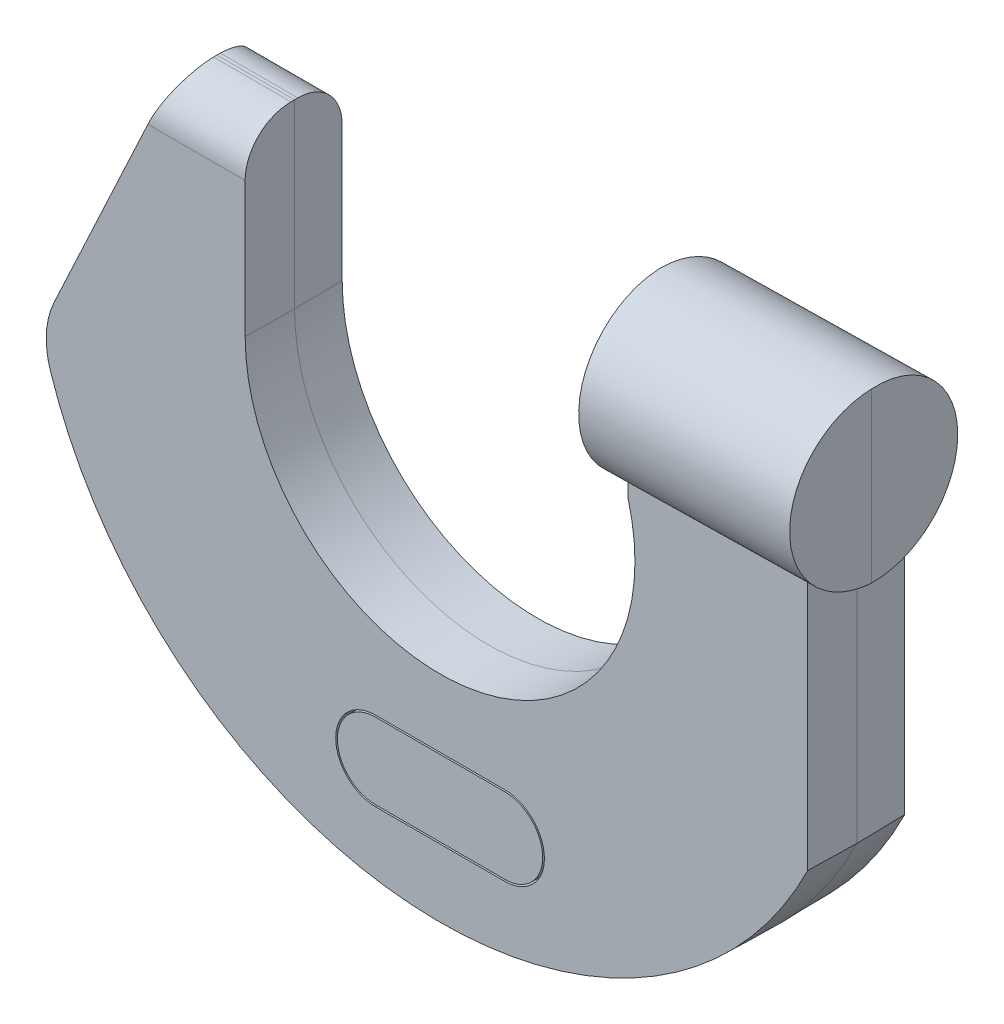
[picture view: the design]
ISO-10303-21;
HEADER;
FILE_DESCRIPTION(('STEP AP214'),'2;1');
FILE_NAME('part.step','',(''),(''),'','','');
FILE_SCHEMA(('AUTOMOTIVE_DESIGN { 1 0 10303 214 1 1 1 1 }'));
ENDSEC;
DATA;
#1=APPLICATION_CONTEXT('core data for automotive mechanical design processes');
#2=APPLICATION_PROTOCOL_DEFINITION('international standard','automotive_design',2000,#1);
#3=PRODUCT_CONTEXT('',#1,'mechanical');
#4=PRODUCT('Part','Part','',(#3));
#5=PRODUCT_RELATED_PRODUCT_CATEGORY('part','',(#4));
#6=PRODUCT_DEFINITION_FORMATION('','',#4);
#7=PRODUCT_DEFINITION_CONTEXT('part definition',#1,'design');
#8=PRODUCT_DEFINITION('design','',#6,#7);
#9=PRODUCT_DEFINITION_SHAPE('','',#8);
#10=(LENGTH_UNIT() NAMED_UNIT(*) SI_UNIT(.MILLI.,.METRE.));
#11=(NAMED_UNIT(*) PLANE_ANGLE_UNIT() SI_UNIT($,.RADIAN.));
#12=(NAMED_UNIT(*) SI_UNIT($,.STERADIAN.) SOLID_ANGLE_UNIT());
#13=UNCERTAINTY_MEASURE_WITH_UNIT(LENGTH_MEASURE(1.E-05),#10,'distance_accuracy_value','');
#14=(GEOMETRIC_REPRESENTATION_CONTEXT(3) GLOBAL_UNCERTAINTY_ASSIGNED_CONTEXT((#13)) GLOBAL_UNIT_ASSIGNED_CONTEXT((#10,
#11,#12)) REPRESENTATION_CONTEXT('',''));
#15=CARTESIAN_POINT('',(0.,0.,0.));
#16=DIRECTION('',(0.,0.,1.));
#17=DIRECTION('',(1.,0.,0.));
#18=AXIS2_PLACEMENT_3D('',#15,#16,#17);
#19=CARTESIAN_POINT('',(-5.,-20.375,0.));
#20=DIRECTION('',(0.,0.999847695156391,0.0174524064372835));
#21=DIRECTION('',(0.,-0.0174524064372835,0.999847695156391));
#22=AXIS2_PLACEMENT_3D('',#19,#20,#21);
#23=PLANE('',#22);
#24=DIRECTION('',(1.,0.,0.));
#25=VECTOR('',#24,1.);
#26=CARTESIAN_POINT('',(0.,-20.375,0.));
#27=LINE('',#26,#25);
#28=CARTESIAN_POINT('',(-5.,-20.375,0.));
#29=VERTEX_POINT('',#28);
#30=CARTESIAN_POINT('',(5.,-20.375,0.));
#31=VERTEX_POINT('',#30);
#32=EDGE_CURVE('E196',#29,#31,#27,.T.);
#33=ORIENTED_EDGE('',*,*,#32,.F.);
#34=DIRECTION('',(0.,0.0174524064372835,-0.999847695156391));
#35=VECTOR('',#34,1.);
#36=CARTESIAN_POINT('',(-5.,-20.375,0.));
#37=LINE('',#36,#35);
#38=CARTESIAN_POINT('',(-5.,-20.4404564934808,3.75));
#39=VERTEX_POINT('',#38);
#40=EDGE_CURVE('E203',#39,#29,#37,.T.);
#41=ORIENTED_EDGE('',*,*,#40,.F.);
#42=DIRECTION('',(1.,0.,0.));
#43=VECTOR('',#42,1.);
#44=CARTESIAN_POINT('',(-5.,-20.4404564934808,3.75));
#45=LINE('',#44,#43);
#46=CARTESIAN_POINT('',(5.,-20.4404564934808,3.75));
#47=VERTEX_POINT('',#46);
#48=EDGE_CURVE('E187',#39,#47,#45,.T.);
#49=ORIENTED_EDGE('',*,*,#48,.T.);
#50=DIRECTION('',(0.,0.0174524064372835,-0.999847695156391));
#51=VECTOR('',#50,1.);
#52=CARTESIAN_POINT('',(5.,-20.375,0.));
#53=LINE('',#52,#51);
#54=EDGE_CURVE('E198',#47,#31,#53,.T.);
#55=ORIENTED_EDGE('',*,*,#54,.T.);
#56=EDGE_LOOP('',(#33,#41,#49,#55));
#57=FACE_BOUND('',#56,.T.);
#58=ADVANCED_FACE('F126',(#57),#23,.T.);
#59=CARTESIAN_POINT('',(-5.,-23.375,0.));
#60=DIRECTION('',(0.,0.,-1.));
#61=DIRECTION('',(1.,0.,0.));
#62=AXIS2_PLACEMENT_3D('',#59,#60,#61);
#63=CONICAL_SURFACE('',#62,3.,0.0174532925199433);
#64=CARTESIAN_POINT('',(-5.,-23.375,0.));
#65=DIRECTION('',(0.,0.,1.));
#66=DIRECTION('',(1.,0.,0.));
#67=AXIS2_PLACEMENT_3D('',#64,#65,#66);
#68=CIRCLE('',#67,3.);
#69=CARTESIAN_POINT('',(-5.,-26.375,0.));
#70=VERTEX_POINT('',#69);
#71=EDGE_CURVE('E195',#29,#70,#68,.T.);
#72=ORIENTED_EDGE('',*,*,#71,.T.);
#73=DIRECTION('',(0.,-0.0174524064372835,-0.999847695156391));
#74=VECTOR('',#73,1.);
#75=CARTESIAN_POINT('',(-5.,-26.375,0.));
#76=LINE('',#75,#74);
#77=CARTESIAN_POINT('',(-5.,-26.3095435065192,3.75));
#78=VERTEX_POINT('',#77);
#79=EDGE_CURVE('E177',#78,#70,#76,.T.);
#80=ORIENTED_EDGE('',*,*,#79,.F.);
#81=CARTESIAN_POINT('',(-5.,-23.375,3.75));
#82=DIRECTION('',(0.,0.,1.));
#83=DIRECTION('',(1.,0.,0.));
#84=AXIS2_PLACEMENT_3D('',#81,#82,#83);
#85=CIRCLE('',#84,2.93454350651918);
#86=EDGE_CURVE('E181',#39,#78,#85,.T.);
#87=ORIENTED_EDGE('',*,*,#86,.F.);
#88=ORIENTED_EDGE('',*,*,#40,.T.);
#89=EDGE_LOOP('',(#72,#80,#87,#88));
#90=FACE_BOUND('',#89,.T.);
#91=ADVANCED_FACE('F193',(#90),#63,.T.);
#92=CARTESIAN_POINT('',(-5.,-23.375,3.75));
#93=DIRECTION('',(0.,0.,1.));
#94=DIRECTION('',(1.,0.,0.));
#95=AXIS2_PLACEMENT_3D('',#92,#93,#94);
#96=PLANE('',#95);
#97=ORIENTED_EDGE('',*,*,#86,.T.);
#98=DIRECTION('',(-1.,0.,0.));
#99=VECTOR('',#98,1.);
#100=CARTESIAN_POINT('',(-5.,-26.3095435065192,3.75));
#101=LINE('',#100,#99);
#102=CARTESIAN_POINT('',(5.,-26.3095435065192,3.75));
#103=VERTEX_POINT('',#102);
#104=EDGE_CURVE('E169',#78,#103,#101,.F.);
#105=ORIENTED_EDGE('',*,*,#104,.T.);
#106=CARTESIAN_POINT('',(5.,-23.375,3.75));
#107=DIRECTION('',(0.,0.,1.));
#108=DIRECTION('',(1.,0.,0.));
#109=AXIS2_PLACEMENT_3D('',#106,#107,#108);
#110=CIRCLE('',#109,2.93454350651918);
#111=EDGE_CURVE('E182',#103,#47,#110,.T.);
#112=ORIENTED_EDGE('',*,*,#111,.T.);
#113=ORIENTED_EDGE('',*,*,#48,.F.);
#114=EDGE_LOOP('',(#97,#105,#112,#113));
#115=FACE_BOUND('',#114,.T.);
#116=ADVANCED_FACE('F128',(#115),#96,.T.);
#117=CARTESIAN_POINT('',(5.,-23.375,0.));
#118=DIRECTION('',(0.,0.,-1.));
#119=DIRECTION('',(1.,0.,0.));
#120=AXIS2_PLACEMENT_3D('',#117,#118,#119);
#121=CONICAL_SURFACE('',#120,3.,0.0174532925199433);
#122=CARTESIAN_POINT('',(5.,-23.375,0.));
#123=DIRECTION('',(0.,0.,1.));
#124=DIRECTION('',(1.,0.,0.));
#125=AXIS2_PLACEMENT_3D('',#122,#123,#124);
#126=CIRCLE('',#125,3.);
#127=CARTESIAN_POINT('',(5.,-26.375,0.));
#128=VERTEX_POINT('',#127);
#129=EDGE_CURVE('E130',#128,#31,#126,.T.);
#130=ORIENTED_EDGE('',*,*,#129,.T.);
#131=ORIENTED_EDGE('',*,*,#54,.F.);
#132=ORIENTED_EDGE('',*,*,#111,.F.);
#133=DIRECTION('',(0.,-0.0174524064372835,-0.999847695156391));
#134=VECTOR('',#133,1.);
#135=CARTESIAN_POINT('',(5.,-26.375,0.));
#136=LINE('',#135,#134);
#137=EDGE_CURVE('E179',#103,#128,#136,.T.);
#138=ORIENTED_EDGE('',*,*,#137,.T.);
#139=EDGE_LOOP('',(#130,#131,#132,#138));
#140=FACE_BOUND('',#139,.T.);
#141=ADVANCED_FACE('F213',(#140),#121,.T.);
#142=CARTESIAN_POINT('',(-5.,-26.375,0.));
#143=DIRECTION('',(0.,-0.999847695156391,0.0174524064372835));
#144=DIRECTION('',(0.,-0.0174524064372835,-0.999847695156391));
#145=AXIS2_PLACEMENT_3D('',#142,#143,#144);
#146=PLANE('',#145);
#147=DIRECTION('',(1.,0.,0.));
#148=VECTOR('',#147,1.);
#149=CARTESIAN_POINT('',(0.,-26.375,0.));
#150=LINE('',#149,#148);
#151=EDGE_CURVE('E206',#70,#128,#150,.T.);
#152=ORIENTED_EDGE('',*,*,#151,.T.);
#153=ORIENTED_EDGE('',*,*,#137,.F.);
#154=ORIENTED_EDGE('',*,*,#104,.F.);
#155=ORIENTED_EDGE('',*,*,#79,.T.);
#156=EDGE_LOOP('',(#152,#153,#154,#155));
#157=FACE_BOUND('',#156,.T.);
#158=ADVANCED_FACE('F174',(#157),#146,.T.);
#159=CARTESIAN_POINT('',(-5.,-26.375,0.));
#160=DIRECTION('',(0.,-0.999847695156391,-0.0174524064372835));
#161=DIRECTION('',(0.,0.0174524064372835,-0.999847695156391));
#162=AXIS2_PLACEMENT_3D('',#159,#160,#161);
#163=PLANE('',#162);
#164=ORIENTED_EDGE('',*,*,#151,.F.);
#165=DIRECTION('',(0.,-0.0174524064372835,0.999847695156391));
#166=VECTOR('',#165,1.);
#167=CARTESIAN_POINT('',(-5.,-26.375,0.));
#168=LINE('',#167,#166);
#169=CARTESIAN_POINT('',(-5.,-26.3095435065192,-3.75));
#170=VERTEX_POINT('',#169);
#171=EDGE_CURVE('E145',#170,#70,#168,.T.);
#172=ORIENTED_EDGE('',*,*,#171,.F.);
#173=DIRECTION('',(1.,0.,0.));
#174=VECTOR('',#173,1.);
#175=CARTESIAN_POINT('',(-5.,-26.3095435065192,-3.75));
#176=LINE('',#175,#174);
#177=CARTESIAN_POINT('',(5.,-26.3095435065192,-3.75));
#178=VERTEX_POINT('',#177);
#179=EDGE_CURVE('E136',#170,#178,#176,.T.);
#180=ORIENTED_EDGE('',*,*,#179,.T.);
#181=DIRECTION('',(0.,-0.0174524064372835,0.999847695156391));
#182=VECTOR('',#181,1.);
#183=CARTESIAN_POINT('',(5.,-26.375,0.));
#184=LINE('',#183,#182);
#185=EDGE_CURVE('E221',#178,#128,#184,.T.);
#186=ORIENTED_EDGE('',*,*,#185,.T.);
#187=EDGE_LOOP('',(#164,#172,#180,#186));
#188=FACE_BOUND('',#187,.T.);
#189=ADVANCED_FACE('F246',(#188),#163,.T.);
#190=CARTESIAN_POINT('',(-5.,-23.375,0.));
#191=DIRECTION('',(0.,0.,1.));
#192=DIRECTION('',(1.,0.,0.));
#193=AXIS2_PLACEMENT_3D('',#190,#191,#192);
#194=CONICAL_SURFACE('',#193,3.,0.0174532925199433);
#195=ORIENTED_EDGE('',*,*,#71,.F.);
#196=DIRECTION('',(0.,0.0174524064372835,0.999847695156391));
#197=VECTOR('',#196,1.);
#198=CARTESIAN_POINT('',(-5.,-20.375,0.));
#199=LINE('',#198,#197);
#200=CARTESIAN_POINT('',(-5.,-20.4404564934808,-3.75));
#201=VERTEX_POINT('',#200);
#202=EDGE_CURVE('E190',#201,#29,#199,.T.);
#203=ORIENTED_EDGE('',*,*,#202,.F.);
#204=CARTESIAN_POINT('',(-5.,-23.375,-3.75));
#205=DIRECTION('',(0.,0.,1.));
#206=DIRECTION('',(1.,0.,0.));
#207=AXIS2_PLACEMENT_3D('',#204,#205,#206);
#208=CIRCLE('',#207,2.93454350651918);
#209=EDGE_CURVE('E13',#201,#170,#208,.T.);
#210=ORIENTED_EDGE('',*,*,#209,.T.);
#211=ORIENTED_EDGE('',*,*,#171,.T.);
#212=EDGE_LOOP('',(#195,#203,#210,#211));
#213=FACE_BOUND('',#212,.T.);
#214=ADVANCED_FACE('F236',(#213),#194,.T.);
#215=CARTESIAN_POINT('',(-5.,-23.375,-3.75));
#216=DIRECTION('',(0.,0.,1.));
#217=DIRECTION('',(1.,0.,0.));
#218=AXIS2_PLACEMENT_3D('',#215,#216,#217);
#219=PLANE('',#218);
#220=ORIENTED_EDGE('',*,*,#209,.F.);
#221=DIRECTION('',(-1.,0.,0.));
#222=VECTOR('',#221,1.);
#223=CARTESIAN_POINT('',(-5.,-20.4404564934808,-3.75));
#224=LINE('',#223,#222);
#225=CARTESIAN_POINT('',(5.,-20.4404564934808,-3.75));
#226=VERTEX_POINT('',#225);
#227=EDGE_CURVE('E232',#201,#226,#224,.F.);
#228=ORIENTED_EDGE('',*,*,#227,.T.);
#229=CARTESIAN_POINT('',(5.,-23.375,-3.75));
#230=DIRECTION('',(0.,0.,1.));
#231=DIRECTION('',(1.,0.,0.));
#232=AXIS2_PLACEMENT_3D('',#229,#230,#231);
#233=CIRCLE('',#232,2.93454350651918);
#234=EDGE_CURVE('E238',#178,#226,#233,.T.);
#235=ORIENTED_EDGE('',*,*,#234,.F.);
#236=ORIENTED_EDGE('',*,*,#179,.F.);
#237=EDGE_LOOP('',(#220,#228,#235,#236));
#238=FACE_BOUND('',#237,.T.);
#239=ADVANCED_FACE('F248',(#238),#219,.F.);
#240=CARTESIAN_POINT('',(5.,-23.375,0.));
#241=DIRECTION('',(0.,0.,1.));
#242=DIRECTION('',(1.,0.,0.));
#243=AXIS2_PLACEMENT_3D('',#240,#241,#242);
#244=CONICAL_SURFACE('',#243,3.,0.0174532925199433);
#245=ORIENTED_EDGE('',*,*,#129,.F.);
#246=ORIENTED_EDGE('',*,*,#185,.F.);
#247=ORIENTED_EDGE('',*,*,#234,.T.);
#248=DIRECTION('',(0.,0.0174524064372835,0.999847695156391));
#249=VECTOR('',#248,1.);
#250=CARTESIAN_POINT('',(5.,-20.375,0.));
#251=LINE('',#250,#249);
#252=EDGE_CURVE('E224',#226,#31,#251,.T.);
#253=ORIENTED_EDGE('',*,*,#252,.T.);
#254=EDGE_LOOP('',(#245,#246,#247,#253));
#255=FACE_BOUND('',#254,.T.);
#256=ADVANCED_FACE('F219',(#255),#244,.T.);
#257=CARTESIAN_POINT('',(-5.,-20.375,0.));
#258=DIRECTION('',(0.,0.999847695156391,-0.0174524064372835));
#259=DIRECTION('',(0.,0.0174524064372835,0.999847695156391));
#260=AXIS2_PLACEMENT_3D('',#257,#258,#259);
#261=PLANE('',#260);
#262=ORIENTED_EDGE('',*,*,#32,.T.);
#263=ORIENTED_EDGE('',*,*,#252,.F.);
#264=ORIENTED_EDGE('',*,*,#227,.F.);
#265=ORIENTED_EDGE('',*,*,#202,.T.);
#266=EDGE_LOOP('',(#262,#263,#264,#265));
#267=FACE_BOUND('',#266,.T.);
#268=ADVANCED_FACE('F231',(#267),#261,.T.);
#269=CLOSED_SHELL('',(#58,#91,#116,#141,#158,#189,#214,#239,#256,#268));
#270=MANIFOLD_SOLID_BREP('B2',#269);
#271=CARTESIAN_POINT('',(-30.1777049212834,-9.89026670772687,0.4026619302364));
#272=CARTESIAN_POINT('',(-30.1827575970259,-9.8747691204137,0.40266193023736));
#273=CARTESIAN_POINT('',(-30.1878102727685,-9.85927153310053,0.402661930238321));
#274=CARTESIAN_POINT('',(-30.1928629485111,-9.84377394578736,0.402661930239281));
#275=CARTESIAN_POINT('',(-30.4454967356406,-9.06889458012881,0.4026619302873));
#276=CARTESIAN_POINT('',(-30.5507182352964,-8.24652745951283,0.402762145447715));
#277=CARTESIAN_POINT('',(-30.4520398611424,-6.61978235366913,0.402762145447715));
#278=CARTESIAN_POINT('',(-30.2481864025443,-5.81616891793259,0.402661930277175));
#279=CARTESIAN_POINT('',(-29.9037472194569,-5.07751670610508,0.402661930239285));
#280=CARTESIAN_POINT('',(-29.8968584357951,-5.06274366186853,0.402661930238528));
#281=CARTESIAN_POINT('',(-29.8899696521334,-5.04797061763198,0.40266193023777));
#282=CARTESIAN_POINT('',(-29.8830808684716,-5.03319757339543,0.402661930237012));
#283=CARTESIAN_POINT('',(-30.0898750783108,-9.86089944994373,-4.90278218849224));
#284=CARTESIAN_POINT('',(-30.0948558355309,-9.84562245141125,-4.90278218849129));
#285=CARTESIAN_POINT('',(-30.099836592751,-9.83034545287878,-4.90278218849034));
#286=CARTESIAN_POINT('',(-30.1048173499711,-9.8150684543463,-4.9027821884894));
#287=CARTESIAN_POINT('',(-30.3538552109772,-9.05121852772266,-4.90278218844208));
#288=CARTESIAN_POINT('',(-30.4575789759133,-8.24055706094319,-4.90268197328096));
#289=CARTESIAN_POINT('',(-30.3603051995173,-6.6369672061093,-4.90268197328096));
#290=CARTESIAN_POINT('',(-30.1593534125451,-5.84479248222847,-4.90278218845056));
#291=CARTESIAN_POINT('',(-29.819816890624,-5.11665406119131,-4.90278218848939));
#292=CARTESIAN_POINT('',(-29.8130261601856,-5.10209129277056,-4.90278218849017));
#293=CARTESIAN_POINT('',(-29.8062354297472,-5.08752852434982,-4.90278218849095));
#294=CARTESIAN_POINT('',(-29.7994446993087,-5.07296575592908,-4.90278218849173));
#295=B_SPLINE_SURFACE_WITH_KNOTS('',1,3,((#271,#272,#273,#274,#275,#276,#277,#278,#279,#280,
#281,#282),(#283,#284,#285,#286,#287,#288,#289,#290,#291,#292,#293,#294)),.UNSPECIFIED.,.F.,.F.,
.F.,(2,2),(4,3,2,3,4),(0.,1.),(-0.01,0.,0.5,1.,1.01),.UNSPECIFIED.);
#296=DIRECTION('',(0.0165928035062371,0.00540974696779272,-0.999847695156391));
#297=VECTOR('',#296,1.);
#298=CARTESIAN_POINT('',(-30.1642253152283,-9.83443372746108,-1.32304419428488));
#299=LINE('',#298,#297);
#300=CARTESIAN_POINT('',(-30.1861806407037,-9.84159531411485,0.));
#301=VERTEX_POINT('',#300);
#302=CARTESIAN_POINT('',(-30.1239477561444,-9.82130687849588,-3.75));
#303=VERTEX_POINT('',#302);
#304=EDGE_CURVE('E398',#301,#303,#299,.T.);
#305=CARTESIAN_POINT('',(-30.171038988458,-9.88803785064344,-2.87920728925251E-12));
#306=CARTESIAN_POINT('',(-30.1760862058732,-9.87255700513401,-1.91985099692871E-12));
#307=CARTESIAN_POINT('',(-30.1811334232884,-9.85707615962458,-9.60548914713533E-13));
#308=CARTESIAN_POINT('',(-30.1861806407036,-9.84159531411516,0.));
#309=CARTESIAN_POINT('',(-30.4385415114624,-9.06755303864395,4.79638030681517E-11));
#310=CARTESIAN_POINT('',(-30.5436493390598,-8.24607433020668,0.000100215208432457));
#311=CARTESIAN_POINT('',(-30.4450775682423,-6.62108661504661,0.000100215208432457));
#312=CARTESIAN_POINT('',(-30.2414443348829,-5.81834133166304,3.79640980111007E-11));
#313=CARTESIAN_POINT('',(-29.8973772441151,-5.08048707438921,0.));
#314=CARTESIAN_POINT('',(-29.8904959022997,-5.06572998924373,-7.56339435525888E-13));
#315=CARTESIAN_POINT('',(-29.8836145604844,-5.05097290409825,-1.51560621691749E-12));
#316=CARTESIAN_POINT('',(-29.876733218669,-5.03621581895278,-2.27487299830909E-12));
#317=B_SPLINE_CURVE_WITH_KNOTS('',3,(#305,#306,#307,#308,#309,#310,#311,#312,#313,#314,#315,
#316),.UNSPECIFIED.,.F.,.F.,(4,3,2,3,4),(-0.01,0.,0.5,1.,1.01),.UNSPECIFIED.);
#318=CARTESIAN_POINT('',(-29.8973772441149,-5.08048707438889,0.));
#319=VERTEX_POINT('',#318);
#320=EDGE_CURVE('E124',#301,#319,#317,.T.);
#321=CARTESIAN_POINT('',(-29.8973772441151,-5.08048707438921,0.));
#322=CARTESIAN_POINT('',(-29.8948994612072,-5.08162692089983,-0.156249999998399));
#323=CARTESIAN_POINT('',(-29.8924216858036,-5.08276678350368,-0.3124999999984));
#324=CARTESIAN_POINT('',(-29.8874661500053,-5.08504654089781,-0.624999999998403));
#325=CARTESIAN_POINT('',(-29.8849883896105,-5.08618643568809,-0.781249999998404));
#326=CARTESIAN_POINT('',(-29.8800328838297,-5.08846625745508,-1.09374999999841));
#327=CARTESIAN_POINT('',(-29.8775551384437,-5.08960618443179,-1.24999999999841));
#328=CARTESIAN_POINT('',(-29.8725996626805,-5.09188607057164,-1.56249999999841));
#329=CARTESIAN_POINT('',(-29.8701219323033,-5.09302602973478,-1.71874999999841));
#330=CARTESIAN_POINT('',(-29.8651664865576,-5.09530598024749,-2.03124999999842));
#331=CARTESIAN_POINT('',(-29.8626887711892,-5.09644597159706,-2.18749999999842));
#332=CARTESIAN_POINT('',(-29.8577333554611,-5.09872598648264,-2.49999999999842));
#333=CARTESIAN_POINT('',(-29.8552556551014,-5.09986601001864,-2.65624999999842));
#334=CARTESIAN_POINT('',(-29.8503002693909,-5.10214608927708,-2.96874999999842));
#335=CARTESIAN_POINT('',(-29.84782258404,-5.10328614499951,-3.12499999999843));
#336=CARTESIAN_POINT('',(-29.842867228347,-5.10556628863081,-3.43749999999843));
#337=CARTESIAN_POINT('',(-29.8403895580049,-5.10670637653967,-3.59374999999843));
#338=CARTESIAN_POINT('',(-29.8379118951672,-5.10784648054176,-3.75));
#339=B_SPLINE_CURVE_WITH_KNOTS('',3,(#321,#322,#323,#324,#325,#326,#327,#328,#329,#330,#331,
#332,#333,#334,#335,#336,#337,#338),.UNSPECIFIED.,.F.,.F.,(4,2,2,2,2,2,2,2,4),(0.,
0.46882140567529,0.937642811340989,1.40646421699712,1.87528562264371,2.34410702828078,
2.81292843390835,3.28174983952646,3.75057124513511),.UNSPECIFIED.);
#340=CARTESIAN_POINT('',(-29.8379118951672,-5.10784648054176,-3.75));
#341=VERTEX_POINT('',#340);
#342=EDGE_CURVE('E519',#341,#319,#339,.F.);
#343=CARTESIAN_POINT('',(-30.1239477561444,-9.82130687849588,-3.75));
#344=CARTESIAN_POINT('',(-30.1885651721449,-9.62302238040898,-3.75));
#345=CARTESIAN_POINT('',(-30.2434313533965,-9.42172796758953,-3.75));
#346=CARTESIAN_POINT('',(-30.3334765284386,-9.01449324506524,-3.75));
#347=CARTESIAN_POINT('',(-30.3686285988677,-8.80854697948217,-3.75));
#348=CARTESIAN_POINT('',(-30.4372160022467,-8.24268287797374,-3.75));
#349=CARTESIAN_POINT('',(-30.4506874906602,-7.88005396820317,-3.75));
#350=CARTESIAN_POINT('',(-30.4248312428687,-7.33869752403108,-3.75));
#351=CARTESIAN_POINT('',(-30.4085013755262,-7.15852291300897,-3.75));
#352=CARTESIAN_POINT('',(-30.3607147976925,-6.8001726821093,-3.75));
#353=CARTESIAN_POINT('',(-30.3292620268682,-6.62199655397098,-3.75));
#354=CARTESIAN_POINT('',(-30.2611399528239,-6.31246037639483,-3.75));
#355=CARTESIAN_POINT('',(-30.2276672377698,-6.18038569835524,-3.75));
#356=CARTESIAN_POINT('',(-30.1712624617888,-5.98406885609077,-3.75));
#357=CARTESIAN_POINT('',(-30.151427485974,-5.91892695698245,-3.75));
#358=CARTESIAN_POINT('',(-30.1097078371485,-5.78930432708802,-3.75));
#359=CARTESIAN_POINT('',(-30.08782324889,-5.72482356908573,-3.75));
#360=CARTESIAN_POINT('',(-30.0420614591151,-5.59670095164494,-3.75));
#361=CARTESIAN_POINT('',(-30.0181878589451,-5.53305780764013,-3.75));
#362=CARTESIAN_POINT('',(-29.9808698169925,-5.43818456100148,-3.75));
#363=CARTESIAN_POINT('',(-29.9681782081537,-5.4066564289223,-3.75));
#364=CARTESIAN_POINT('',(-29.9422965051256,-5.34380684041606,-3.75));
#365=CARTESIAN_POINT('',(-29.9291064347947,-5.31248537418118,-3.75));
#366=CARTESIAN_POINT('',(-29.9022255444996,-5.25006178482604,-3.75));
#367=CARTESIAN_POINT('',(-29.8885347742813,-5.21895964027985,-3.75));
#368=CARTESIAN_POINT('',(-29.8676384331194,-5.17246721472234,-3.75));
#369=CARTESIAN_POINT('',(-29.8606126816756,-5.15699595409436,-3.75));
#370=CARTESIAN_POINT('',(-29.8464160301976,-5.12612002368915,-3.75));
#371=CARTESIAN_POINT('',(-29.8392451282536,-5.1107153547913,-3.75));
#372=CARTESIAN_POINT('',(-29.8248922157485,-5.07991594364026,-3.75));
#373=CARTESIAN_POINT('',(-29.8177102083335,-5.06452119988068,-3.75));
#374=CARTESIAN_POINT('',(-29.803349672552,-5.03373017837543,-3.75));
#375=CARTESIAN_POINT('',(-29.7961711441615,-5.01833390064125,-3.75));
#376=CARTESIAN_POINT('',(-29.7818143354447,-4.98754412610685,-3.75));
#377=CARTESIAN_POINT('',(-29.7746360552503,-4.97215062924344,-3.75));
#378=CARTESIAN_POINT('',(-29.7602794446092,-4.94136352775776,-3.75));
#379=CARTESIAN_POINT('',(-29.7531011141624,-4.92596992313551,-3.75));
#380=CARTESIAN_POINT('',(-29.7459232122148,-4.91057611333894,-3.75));
#381=B_SPLINE_CURVE_WITH_KNOTS('',3,(#343,#344,#345,#346,#347,#348,#349,#350,#351,#352,#353,
#354,#355,#356,#357,#358,#359,#360,#361,#362,#363,#364,#365,#366,#367,#368,#369,#370,#371,#372,
#373,#374,#375,#376,#377,#378,#379,#380),.UNSPECIFIED.,.F.,.F.,(4,2,2,2,2,2,2,2,2,2,2,2,2,2,2,2,
2,2,4),(0.,0.625084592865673,1.2510207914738,2.33363174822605,2.87586935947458,3.41796578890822,
3.82644665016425,4.03070073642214,4.2349463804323,4.43882993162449,4.54078669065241,
4.64273857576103,4.74468035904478,4.79565511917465,4.84663055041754,4.89759351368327,
4.94855612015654,4.99951088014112,5.05046599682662),.UNSPECIFIED.);
#382=EDGE_CURVE('E404',#303,#341,#381,.T.);
#383=ORIENTED_EDGE('',*,*,#304,.F.);
#384=ORIENTED_EDGE('',*,*,#320,.T.);
#385=ORIENTED_EDGE('',*,*,#342,.F.);
#386=ORIENTED_EDGE('',*,*,#382,.F.);
#387=EDGE_LOOP('',(#383,#384,#385,#386));
#388=FACE_BOUND('',#387,.T.);
#389=ADVANCED_FACE('F362',(#388),#295,.F.);
#390=CARTESIAN_POINT('',(13.35,0.,0.));
#391=DIRECTION('',(-0.999847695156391,0.,0.0174524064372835));
#392=DIRECTION('',(0.0174524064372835,0.,0.999847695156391));
#393=AXIS2_PLACEMENT_3D('',#390,#391,#392);
#394=PLANE('',#393);
#395=CARTESIAN_POINT('',(13.35,10.45,0.));
#396=DIRECTION('',(-0.999847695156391,0.,0.0174524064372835));
#397=DIRECTION('',(0.0174524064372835,0.,0.999847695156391));
#398=AXIS2_PLACEMENT_3D('',#395,#396,#397);
#399=CIRCLE('',#398,6.5);
#400=CARTESIAN_POINT('',(13.35,16.95,0.));
#401=VERTEX_POINT('',#400);
#402=CARTESIAN_POINT('',(13.35,3.95,0.));
#403=VERTEX_POINT('',#402);
#404=EDGE_CURVE('E430',#401,#403,#399,.F.);
#405=ORIENTED_EDGE('',*,*,#404,.F.);
#406=DIRECTION('',(0.,-1.,0.));
#407=VECTOR('',#406,1.);
#408=CARTESIAN_POINT('',(13.35,0.,0.));
#409=LINE('',#408,#407);
#410=EDGE_CURVE('E372',#401,#403,#409,.T.);
#411=ORIENTED_EDGE('',*,*,#410,.T.);
#412=EDGE_LOOP('',(#405,#411));
#413=FACE_BOUND('',#412,.T.);
#414=ADVANCED_FACE('F471',(#413),#394,.T.);
#415=CARTESIAN_POINT('',(29.6024753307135,0.,0.));
#416=DIRECTION('',(0.999847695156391,0.,-0.0174524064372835));
#417=DIRECTION('',(-0.0174524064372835,0.,-0.999847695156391));
#418=AXIS2_PLACEMENT_3D('',#415,#416,#417);
#419=PLANE('',#418);
#420=CARTESIAN_POINT('',(29.5975250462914,10.45,-0.283601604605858));
#421=DIRECTION('',(0.999847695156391,0.,-0.0174524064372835));
#422=DIRECTION('',(-0.0174524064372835,0.,-0.999847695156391));
#423=AXIS2_PLACEMENT_3D('',#420,#421,#422);
#424=CIRCLE('',#423,6.5);
#425=CARTESIAN_POINT('',(29.6024753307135,3.95619174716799,0.));
#426=VERTEX_POINT('',#425);
#427=CARTESIAN_POINT('',(29.6024753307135,16.943808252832,0.));
#428=VERTEX_POINT('',#427);
#429=EDGE_CURVE('E420',#426,#428,#424,.T.);
#430=ORIENTED_EDGE('',*,*,#429,.T.);
#431=DIRECTION('',(0.,-1.,0.));
#432=VECTOR('',#431,1.);
#433=CARTESIAN_POINT('',(29.6024753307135,0.,0.));
#434=LINE('',#433,#432);
#435=EDGE_CURVE('E418',#428,#426,#434,.T.);
#436=ORIENTED_EDGE('',*,*,#435,.T.);
#437=EDGE_LOOP('',(#430,#436));
#438=FACE_BOUND('',#437,.T.);
#439=ADVANCED_FACE('F364',(#438),#419,.T.);
#440=CARTESIAN_POINT('',(0.,0.,0.));
#441=DIRECTION('',(0.,0.,-1.));
#442=DIRECTION('',(1.,0.,0.));
#443=AXIS2_PLACEMENT_3D('',#440,#441,#442);
#444=CONICAL_SURFACE('',#443,15.,0.0174532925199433);
#445=CARTESIAN_POINT('',(14.4716828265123,3.95014867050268,-0.063548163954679));
#446=CARTESIAN_POINT('',(14.4713712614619,3.95001904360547,-0.0443729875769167));
#447=CARTESIAN_POINT('',(14.4710365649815,3.94997418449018,-0.0251982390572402));
#448=CARTESIAN_POINT('',(14.4706412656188,3.95001827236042,-0.00401599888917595));
#449=CARTESIAN_POINT('',(14.4706035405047,3.95002338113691,-0.00200808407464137));
#450=CARTESIAN_POINT('',(14.4705655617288,3.95002941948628,-1.73952045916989E-07));
#451=B_SPLINE_CURVE_WITH_KNOTS('',3,(#445,#446,#447,#448,#449,#450),.UNSPECIFIED.,.F.,.F.,(4,2,
4),(0.,0.0575331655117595,0.0635579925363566),.UNSPECIFIED.);
#452=CARTESIAN_POINT('',(14.4716828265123,3.9501486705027,-0.063548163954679));
#453=VERTEX_POINT('',#452);
#454=CARTESIAN_POINT('',(14.4705735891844,3.95002206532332,0.));
#455=VERTEX_POINT('',#454);
#456=EDGE_CURVE('E803',#453,#455,#451,.T.);
#457=ORIENTED_EDGE('',*,*,#456,.F.);
#458=CARTESIAN_POINT('',(14.5360300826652,3.95876354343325,-3.75));
#459=CARTESIAN_POINT('',(14.525120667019,3.95730457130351,-3.12499999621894));
#460=CARTESIAN_POINT('',(14.5142112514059,3.95584478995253,-2.49999999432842));
#461=CARTESIAN_POINT('',(14.4923924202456,3.95292360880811,-1.24999999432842));
#462=CARTESIAN_POINT('',(14.4814830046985,3.95146220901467,-0.624999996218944));
#463=CARTESIAN_POINT('',(14.4705735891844,3.94999999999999,0.));
#464=B_SPLINE_CURVE_WITH_KNOTS('',3,(#458,#459,#460,#461,#462,#463),.UNSPECIFIED.,.F.,.F.,(4,2,
4),(0.,1.87529073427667,3.75058146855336),.UNSPECIFIED.);
#465=CARTESIAN_POINT('',(14.5360300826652,3.95876354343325,-3.75));
#466=VERTEX_POINT('',#465);
#467=EDGE_CURVE('E565',#466,#453,#464,.T.);
#468=ORIENTED_EDGE('',*,*,#467,.F.);
#469=CARTESIAN_POINT('',(0.,0.,-3.75));
#470=DIRECTION('',(0.,0.,1.));
#471=DIRECTION('',(1.,0.,0.));
#472=AXIS2_PLACEMENT_3D('',#469,#470,#471);
#473=CIRCLE('',#472,15.0654564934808);
#474=CARTESIAN_POINT('',(-15.0654564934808,0.,-3.75));
#475=VERTEX_POINT('',#474);
#476=EDGE_CURVE('E956',#475,#466,#473,.T.);
#477=ORIENTED_EDGE('',*,*,#476,.F.);
#478=DIRECTION('',(0.0174524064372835,0.,0.999847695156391));
#479=VECTOR('',#478,1.);
#480=CARTESIAN_POINT('',(-15.,0.,0.));
#481=LINE('',#480,#479);
#482=CARTESIAN_POINT('',(-15.,0.,0.));
#483=VERTEX_POINT('',#482);
#484=EDGE_CURVE('E894',#475,#483,#481,.T.);
#485=ORIENTED_EDGE('',*,*,#484,.T.);
#486=CARTESIAN_POINT('',(0.,0.,0.));
#487=DIRECTION('',(0.,0.,1.));
#488=DIRECTION('',(1.,0.,0.));
#489=AXIS2_PLACEMENT_3D('',#486,#487,#488);
#490=CIRCLE('',#489,15.);
#491=EDGE_CURVE('E626',#483,#455,#490,.T.);
#492=ORIENTED_EDGE('',*,*,#491,.T.);
#493=EDGE_LOOP('',(#457,#468,#477,#485,#492));
#494=FACE_BOUND('',#493,.T.);
#495=ADVANCED_FACE('F891',(#494),#444,.F.);
#496=CARTESIAN_POINT('',(14.4705735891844,0.,0.));
#497=DIRECTION('',(-0.999847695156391,0.,-0.0174524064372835));
#498=DIRECTION('',(-0.0174524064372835,0.,0.999847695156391));
#499=AXIS2_PLACEMENT_3D('',#496,#497,#498);
#500=PLANE('',#499);
#501=CARTESIAN_POINT('',(14.4709151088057,10.45,-0.0195656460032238));
#502=DIRECTION('',(-0.999847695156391,0.,-0.0174524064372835));
#503=DIRECTION('',(-0.0174524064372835,0.,0.999847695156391));
#504=AXIS2_PLACEMENT_3D('',#501,#502,#503);
#505=ELLIPSE('',#504,6.50396203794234,6.5);
#506=CARTESIAN_POINT('',(14.5360300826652,5.12584990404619,-3.75));
#507=VERTEX_POINT('',#506);
#508=EDGE_CURVE('E436',#507,#453,#505,.T.);
#509=ORIENTED_EDGE('',*,*,#508,.F.);
#510=DIRECTION('',(0.,-1.,0.));
#511=VECTOR('',#510,1.);
#512=CARTESIAN_POINT('',(14.5360300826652,0.,-3.75));
#513=LINE('',#512,#511);
#514=EDGE_CURVE('E951',#466,#507,#513,.F.);
#515=ORIENTED_EDGE('',*,*,#514,.F.);
#516=ORIENTED_EDGE('',*,*,#467,.T.);
#517=EDGE_LOOP('',(#509,#515,#516));
#518=FACE_BOUND('',#517,.T.);
#519=ADVANCED_FACE('F750',(#518),#500,.T.);
#520=CARTESIAN_POINT('',(0.,14.,0.));
#521=DIRECTION('',(0.,0.999847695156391,0.0174524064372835));
#522=DIRECTION('',(0.,-0.0174524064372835,0.999847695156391));
#523=AXIS2_PLACEMENT_3D('',#520,#521,#522);
#524=PLANE('',#523);
#525=DIRECTION('',(-0.0111177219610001,0.0174513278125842,-0.999785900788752));
#526=VECTOR('',#525,1.);
#527=CARTESIAN_POINT('',(-20.9995286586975,13.9992601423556,0.0423864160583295));
#528=LINE('',#527,#526);
#529=CARTESIAN_POINT('',(-20.9970870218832,13.9954275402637,0.261956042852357));
#530=VERTEX_POINT('',#529);
#531=CARTESIAN_POINT('',(-21.,14.,0.));
#532=VERTEX_POINT('',#531);
#533=EDGE_CURVE('E701',#530,#532,#528,.T.);
#534=ORIENTED_EDGE('',*,*,#533,.F.);
#535=DIRECTION('',(-1.,0.,0.));
#536=VECTOR('',#535,1.);
#537=CARTESIAN_POINT('',(-15.0654564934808,13.9954275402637,0.261956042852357));
#538=LINE('',#537,#536);
#539=CARTESIAN_POINT('',(-15.0045724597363,13.9954275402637,0.261956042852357));
#540=VERTEX_POINT('',#539);
#541=EDGE_CURVE('E783',#530,#540,#538,.F.);
#542=ORIENTED_EDGE('',*,*,#541,.T.);
#543=DIRECTION('',(0.0174497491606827,0.0174497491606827,-0.999695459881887));
#544=VECTOR('',#543,1.);
#545=CARTESIAN_POINT('',(-14.9954325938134,14.0045674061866,-0.261666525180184));
#546=LINE('',#545,#544);
#547=CARTESIAN_POINT('',(-15.,14.,0.));
#548=VERTEX_POINT('',#547);
#549=EDGE_CURVE('E704',#540,#548,#546,.T.);
#550=ORIENTED_EDGE('',*,*,#549,.T.);
#551=DIRECTION('',(-1.,0.,0.));
#552=VECTOR('',#551,1.);
#553=CARTESIAN_POINT('',(0.,14.,0.));
#554=LINE('',#553,#552);
#555=EDGE_CURVE('E640',#548,#532,#554,.T.);
#556=ORIENTED_EDGE('',*,*,#555,.T.);
#557=EDGE_LOOP('',(#534,#542,#550,#556));
#558=FACE_BOUND('',#557,.T.);
#559=ADVANCED_FACE('F747',(#558),#524,.T.);
#560=CARTESIAN_POINT('',(0.,0.,3.75));
#561=DIRECTION('',(0.,0.,1.));
#562=DIRECTION('',(1.,0.,0.));
#563=AXIS2_PLACEMENT_3D('',#560,#561,#562);
#564=PLANE('',#563);
#565=CARTESIAN_POINT('',(5.,-23.375,3.75));
#566=DIRECTION('',(0.,0.,1.));
#567=DIRECTION('',(1.,0.,0.));
#568=AXIS2_PLACEMENT_3D('',#565,#566,#567);
#569=CIRCLE('',#568,3.06545649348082);
#570=CARTESIAN_POINT('',(5.,-26.4404564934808,3.75));
#571=VERTEX_POINT('',#570);
#572=CARTESIAN_POINT('',(5.,-20.3095435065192,3.75));
#573=VERTEX_POINT('',#572);
#574=EDGE_CURVE('E690',#571,#573,#569,.T.);
#575=ORIENTED_EDGE('',*,*,#574,.F.);
#576=DIRECTION('',(1.,0.,0.));
#577=VECTOR('',#576,1.);
#578=CARTESIAN_POINT('',(0.,-26.4404564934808,3.75));
#579=LINE('',#578,#577);
#580=CARTESIAN_POINT('',(-5.,-26.4404564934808,3.75));
#581=VERTEX_POINT('',#580);
#582=EDGE_CURVE('E693',#581,#571,#579,.T.);
#583=ORIENTED_EDGE('',*,*,#582,.F.);
#584=CARTESIAN_POINT('',(-5.,-23.375,3.75));
#585=DIRECTION('',(0.,0.,1.));
#586=DIRECTION('',(1.,0.,0.));
#587=AXIS2_PLACEMENT_3D('',#584,#585,#586);
#588=CIRCLE('',#587,3.06545649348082);
#589=CARTESIAN_POINT('',(-5.,-20.3095435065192,3.75));
#590=VERTEX_POINT('',#589);
#591=EDGE_CURVE('E697',#590,#581,#588,.T.);
#592=ORIENTED_EDGE('',*,*,#591,.F.);
#593=DIRECTION('',(-1.,0.,0.));
#594=VECTOR('',#593,1.);
#595=CARTESIAN_POINT('',(0.,-20.3095435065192,3.75));
#596=LINE('',#595,#594);
#597=EDGE_CURVE('E675',#590,#573,#596,.F.);
#598=ORIENTED_EDGE('',*,*,#597,.T.);
#599=EDGE_LOOP('',(#575,#583,#592,#598));
#600=FACE_BOUND('',#599,.T.);
#601=DIRECTION('',(0.422618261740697,0.906307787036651,0.));
#602=VECTOR('',#601,1.);
#603=CARTESIAN_POINT('',(-22.5522572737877,10.5162902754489,3.75));
#604=LINE('',#603,#602);
#605=CARTESIAN_POINT('',(-22.5850489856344,10.4459682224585,3.75));
#606=VERTEX_POINT('',#605);
#607=CARTESIAN_POINT('',(-29.8380535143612,-5.10815018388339,3.75));
#608=VERTEX_POINT('',#607);
#609=EDGE_CURVE('E700',#606,#608,#604,.F.);
#610=ORIENTED_EDGE('',*,*,#609,.T.);
#611=CARTESIAN_POINT('',(-29.8380535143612,-5.10815018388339,3.75));
#612=CARTESIAN_POINT('',(-29.925051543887,-5.29478189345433,3.75));
#613=CARTESIAN_POINT('',(-30.0029668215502,-5.48547389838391,3.75));
#614=CARTESIAN_POINT('',(-30.1403068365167,-5.8737185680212,3.75));
#615=CARTESIAN_POINT('',(-30.1997044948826,-6.07128081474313,3.75));
#616=CARTESIAN_POINT('',(-30.3369294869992,-6.62193811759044,3.75));
#617=CARTESIAN_POINT('',(-30.3950194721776,-6.98025792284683,3.75));
#618=CARTESIAN_POINT('',(-30.4361033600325,-7.52083747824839,3.75));
#619=CARTESIAN_POINT('',(-30.4421085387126,-7.70169954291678,3.75));
#620=CARTESIAN_POINT('',(-30.4388457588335,-8.06330667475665,3.75));
#621=CARTESIAN_POINT('',(-30.4295816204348,-8.24405175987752,3.75));
#622=CARTESIAN_POINT('',(-30.4002376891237,-8.5582548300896,3.75));
#623=CARTESIAN_POINT('',(-30.3835114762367,-8.69203772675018,3.75));
#624=CARTESIAN_POINT('',(-30.3521850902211,-8.8917170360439,3.75));
#625=CARTESIAN_POINT('',(-30.3407032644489,-8.95811180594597,3.75));
#626=CARTESIAN_POINT('',(-30.3156681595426,-9.09050921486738,3.75));
#627=CARTESIAN_POINT('',(-30.3021149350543,-9.15651186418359,3.75));
#628=CARTESIAN_POINT('',(-30.2729705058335,-9.28794659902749,3.75));
#629=CARTESIAN_POINT('',(-30.2573828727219,-9.35337947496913,3.75));
#630=CARTESIAN_POINT('',(-30.2324658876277,-9.45113788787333,3.75));
#631=CARTESIAN_POINT('',(-30.2239037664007,-9.4836607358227,3.75));
#632=CARTESIAN_POINT('',(-30.2062691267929,-9.54856675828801,3.75));
#633=CARTESIAN_POINT('',(-30.1971966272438,-9.58094993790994,3.75));
#634=CARTESIAN_POINT('',(-30.1785417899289,-9.64556844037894,3.75));
#635=CARTESIAN_POINT('',(-30.1689594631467,-9.67780376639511,3.75));
#636=CARTESIAN_POINT('',(-30.1542056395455,-9.72604115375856,3.75));
#637=CARTESIAN_POINT('',(-30.149224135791,-9.74210155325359,3.75));
#638=CARTESIAN_POINT('',(-30.1391320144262,-9.77418185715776,3.75));
#639=CARTESIAN_POINT('',(-30.1340213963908,-9.79020176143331,3.75));
#640=CARTESIAN_POINT('',(-30.123682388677,-9.82220015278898,3.75));
#641=CARTESIAN_POINT('',(-30.1184540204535,-9.83817864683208,3.75));
#642=CARTESIAN_POINT('',(-30.1080188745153,-9.8701426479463,3.75));
#643=CARTESIAN_POINT('',(-30.1028120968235,-9.88612815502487,3.75));
#644=CARTESIAN_POINT('',(-30.092393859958,-9.91809521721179,3.75));
#645=CARTESIAN_POINT('',(-30.0871824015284,-9.93407677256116,3.75));
#646=CARTESIAN_POINT('',(-30.0767594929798,-9.9660398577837,3.75));
#647=CARTESIAN_POINT('',(-30.0715480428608,-9.98202138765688,3.75));
#648=CARTESIAN_POINT('',(-30.0663392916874,-9.99800379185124,3.75));
#649=B_SPLINE_CURVE_WITH_KNOTS('',3,(#611,#612,#613,#614,#615,#616,#617,#618,#619,#620,#621,
#622,#623,#624,#625,#626,#627,#628,#629,#630,#631,#632,#633,#634,#635,#636,#637,#638,#639,#640,
#641,#642,#643,#644,#645,#646,#647,#648),.UNSPECIFIED.,.F.,.F.,(4,2,2,2,2,2,2,2,2,2,2,2,2,2,2,2,
2,2,4),(0.,0.61719291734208,1.23528418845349,2.31823981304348,2.86062368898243,3.40287188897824,
3.80708456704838,4.00919605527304,4.21130221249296,4.41305820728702,4.51394781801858,
4.61483370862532,4.71571742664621,4.76616267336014,4.81660808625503,4.86704438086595,
4.91748072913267,4.96791012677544,5.01833944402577),.UNSPECIFIED.);
#650=CARTESIAN_POINT('',(-30.1239480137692,-9.82130608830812,3.75));
#651=VERTEX_POINT('',#650);
#652=EDGE_CURVE('E424',#608,#651,#649,.T.);
#653=ORIENTED_EDGE('',*,*,#652,.T.);
#654=CARTESIAN_POINT('',(0.,0.,3.75));
#655=DIRECTION('',(0.,0.,1.));
#656=DIRECTION('',(1.,0.,0.));
#657=AXIS2_PLACEMENT_3D('',#654,#655,#656);
#658=CIRCLE('',#657,31.6845435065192);
#659=CARTESIAN_POINT('',(28.4139699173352,-14.0198648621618,3.75));
#660=VERTEX_POINT('',#659);
#661=EDGE_CURVE('E823',#651,#660,#658,.T.);
#662=ORIENTED_EDGE('',*,*,#661,.T.);
#663=DIRECTION('',(0.,-1.,0.));
#664=VECTOR('',#663,1.);
#665=CARTESIAN_POINT('',(28.4139699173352,0.,3.75));
#666=LINE('',#665,#664);
#667=CARTESIAN_POINT('',(28.4139699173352,5.33617590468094,3.75));
#668=VERTEX_POINT('',#667);
#669=EDGE_CURVE('E825',#668,#660,#666,.T.);
#670=ORIENTED_EDGE('',*,*,#669,.F.);
#671=CARTESIAN_POINT('',(-201.487356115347,10.45,3.75));
#672=DIRECTION('',(0.,0.,1.));
#673=DIRECTION('',(-1.,0.,0.));
#674=AXIS2_PLACEMENT_3D('',#671,#672,#673);
#675=ELLIPSE('',#674,372.441475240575,6.5);
#676=CARTESIAN_POINT('',(14.5360300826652,5.15508400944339,3.75));
#677=VERTEX_POINT('',#676);
#678=EDGE_CURVE('E862',#668,#677,#675,.F.);
#679=ORIENTED_EDGE('',*,*,#678,.T.);
#680=DIRECTION('',(0.,1.,0.));
#681=VECTOR('',#680,1.);
#682=CARTESIAN_POINT('',(14.5360300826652,0.,3.75));
#683=LINE('',#682,#681);
#684=CARTESIAN_POINT('',(14.5360300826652,3.95876354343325,3.75));
#685=VERTEX_POINT('',#684);
#686=EDGE_CURVE('E826',#685,#677,#683,.T.);
#687=ORIENTED_EDGE('',*,*,#686,.F.);
#688=CARTESIAN_POINT('',(0.,0.,3.75));
#689=DIRECTION('',(0.,0.,1.));
#690=DIRECTION('',(1.,0.,0.));
#691=AXIS2_PLACEMENT_3D('',#688,#689,#690);
#692=CIRCLE('',#691,15.0654564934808);
#693=CARTESIAN_POINT('',(-15.0654564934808,0.,3.75));
#694=VERTEX_POINT('',#693);
#695=EDGE_CURVE('E831',#694,#685,#692,.T.);
#696=ORIENTED_EDGE('',*,*,#695,.F.);
#697=DIRECTION('',(0.,-1.,0.));
#698=VECTOR('',#697,1.);
#699=CARTESIAN_POINT('',(-15.0654564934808,0.,3.75));
#700=LINE('',#699,#698);
#701=CARTESIAN_POINT('',(-15.0654564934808,10.4459682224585,3.75));
#702=VERTEX_POINT('',#701);
#703=EDGE_CURVE('E686',#694,#702,#700,.F.);
#704=ORIENTED_EDGE('',*,*,#703,.T.);
#705=DIRECTION('',(1.,0.,0.));
#706=VECTOR('',#705,1.);
#707=CARTESIAN_POINT('',(-20.9582996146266,10.4459682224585,3.75));
#708=LINE('',#707,#706);
#709=EDGE_CURVE('E785',#702,#606,#708,.F.);
#710=ORIENTED_EDGE('',*,*,#709,.T.);
#711=EDGE_LOOP('',(#610,#653,#662,#670,#679,#687,#696,#704,#710));
#712=FACE_BOUND('',#711,.T.);
#713=ADVANCED_FACE('F749',(#600,#712),#564,.T.);
#714=CARTESIAN_POINT('',(-15.,0.,0.));
#715=DIRECTION('',(0.999847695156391,0.,0.0174524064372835));
#716=DIRECTION('',(0.0174524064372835,0.,-0.999847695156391));
#717=AXIS2_PLACEMENT_3D('',#714,#715,#716);
#718=PLANE('',#717);
#719=ORIENTED_EDGE('',*,*,#549,.F.);
#720=CARTESIAN_POINT('',(-15.0034910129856,10.4459682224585,0.2));
#721=DIRECTION('',(0.999847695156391,0.,0.0174524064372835));
#722=DIRECTION('',(-0.0174524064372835,0.,0.999847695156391));
#723=AXIS2_PLACEMENT_3D('',#720,#721,#722);
#724=ELLIPSE('',#723,3.55054076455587,3.55);
#725=EDGE_CURVE('E769',#540,#702,#724,.T.);
#726=ORIENTED_EDGE('',*,*,#725,.T.);
#727=ORIENTED_EDGE('',*,*,#703,.F.);
#728=DIRECTION('',(0.0174524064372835,0.,-0.999847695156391));
#729=VECTOR('',#728,1.);
#730=CARTESIAN_POINT('',(-15.,0.,0.));
#731=LINE('',#730,#729);
#732=EDGE_CURVE('E707',#694,#483,#731,.T.);
#733=ORIENTED_EDGE('',*,*,#732,.T.);
#734=DIRECTION('',(0.,1.,0.));
#735=VECTOR('',#734,1.);
#736=CARTESIAN_POINT('',(-15.,0.,0.));
#737=LINE('',#736,#735);
#738=EDGE_CURVE('E633',#483,#548,#737,.T.);
#739=ORIENTED_EDGE('',*,*,#738,.T.);
#740=EDGE_LOOP('',(#719,#726,#727,#733,#739));
#741=FACE_BOUND('',#740,.T.);
#742=ADVANCED_FACE('F752',(#741),#718,.T.);
#743=CARTESIAN_POINT('',(0.,0.,0.));
#744=DIRECTION('',(0.,0.,1.));
#745=DIRECTION('',(1.,0.,0.));
#746=AXIS2_PLACEMENT_3D('',#743,#744,#745);
#747=CONICAL_SURFACE('',#746,15.,0.0174532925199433);
#748=ORIENTED_EDGE('',*,*,#491,.F.);
#749=ORIENTED_EDGE('',*,*,#732,.F.);
#750=ORIENTED_EDGE('',*,*,#695,.T.);
#751=CARTESIAN_POINT('',(14.5360300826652,3.95876354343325,3.75));
#752=CARTESIAN_POINT('',(14.525120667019,3.95730457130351,3.12499999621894));
#753=CARTESIAN_POINT('',(14.5142112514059,3.95584478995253,2.49999999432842));
#754=CARTESIAN_POINT('',(14.4923924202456,3.95292360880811,1.24999999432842));
#755=CARTESIAN_POINT('',(14.4814830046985,3.95146220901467,0.624999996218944));
#756=CARTESIAN_POINT('',(14.4705735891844,3.94999999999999,0.));
#757=B_SPLINE_CURVE_WITH_KNOTS('',3,(#751,#752,#753,#754,#755,#756),.UNSPECIFIED.,.F.,.F.,(4,2,
4),(0.,1.87529073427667,3.75058146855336),.UNSPECIFIED.);
#758=EDGE_CURVE('E710',#685,#455,#757,.T.);
#759=ORIENTED_EDGE('',*,*,#758,.T.);
#760=EDGE_LOOP('',(#748,#749,#750,#759));
#761=FACE_BOUND('',#760,.T.);
#762=ADVANCED_FACE('F754',(#761),#747,.F.);
#763=CARTESIAN_POINT('',(14.4705735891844,0.,0.));
#764=DIRECTION('',(-0.999847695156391,0.,0.0174524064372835));
#765=DIRECTION('',(0.0174524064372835,0.,0.999847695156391));
#766=AXIS2_PLACEMENT_3D('',#763,#764,#765);
#767=PLANE('',#766);
#768=ORIENTED_EDGE('',*,*,#686,.T.);
#769=CARTESIAN_POINT('',(14.4702322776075,10.45,-0.0195537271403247));
#770=DIRECTION('',(-0.999847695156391,0.,0.0174524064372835));
#771=DIRECTION('',(0.0174524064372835,0.,0.999847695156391));
#772=AXIS2_PLACEMENT_3D('',#769,#770,#771);
#773=CIRCLE('',#772,6.5);
#774=EDGE_CURVE('E694',#677,#455,#773,.F.);
#775=ORIENTED_EDGE('',*,*,#774,.T.);
#776=ORIENTED_EDGE('',*,*,#758,.F.);
#777=EDGE_LOOP('',(#768,#775,#776));
#778=FACE_BOUND('',#777,.T.);
#779=ADVANCED_FACE('F730',(#778),#767,.T.);
#780=CARTESIAN_POINT('',(28.479426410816,0.,0.));
#781=DIRECTION('',(0.999847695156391,0.,0.0174524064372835));
#782=DIRECTION('',(0.0174524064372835,0.,-0.999847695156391));
#783=AXIS2_PLACEMENT_3D('',#780,#781,#782);
#784=PLANE('',#783);
#785=DIRECTION('',(0.,-1.,0.));
#786=VECTOR('',#785,1.);
#787=CARTESIAN_POINT('',(28.479426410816,0.,0.));
#788=LINE('',#787,#786);
#789=CARTESIAN_POINT('',(28.479426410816,3.95536526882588,0.));
#790=VERTEX_POINT('',#789);
#791=CARTESIAN_POINT('',(28.479426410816,-14.0351263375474,0.));
#792=VERTEX_POINT('',#791);
#793=EDGE_CURVE('E615',#790,#792,#788,.T.);
#794=ORIENTED_EDGE('',*,*,#793,.F.);
#795=CARTESIAN_POINT('',(28.4840374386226,10.45,-0.264165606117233));
#796=DIRECTION('',(0.999847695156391,0.,0.0174524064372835));
#797=DIRECTION('',(-0.0174524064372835,0.,0.999847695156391));
#798=AXIS2_PLACEMENT_3D('',#795,#796,#797);
#799=ELLIPSE('',#798,6.50396203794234,6.5);
#800=EDGE_CURVE('E867',#790,#668,#799,.F.);
#801=ORIENTED_EDGE('',*,*,#800,.T.);
#802=ORIENTED_EDGE('',*,*,#669,.T.);
#803=CARTESIAN_POINT('',(28.4139699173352,-14.0198648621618,3.75));
#804=CARTESIAN_POINT('',(28.4248793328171,-14.022409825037,3.12500000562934));
#805=CARTESIAN_POINT('',(28.4357887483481,-14.0249540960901,2.50000000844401));
#806=CARTESIAN_POINT('',(28.4576075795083,-14.0300412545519,1.25000000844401));
#807=CARTESIAN_POINT('',(28.4685169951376,-14.0325841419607,0.625000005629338));
#808=CARTESIAN_POINT('',(28.479426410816,-14.0351263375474,0.));
#809=B_SPLINE_CURVE_WITH_KNOTS('',3,(#803,#804,#805,#806,#807,#808),.UNSPECIFIED.,.F.,.F.,(4,2,
4),(0.,1.87530114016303,3.75060228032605),.UNSPECIFIED.);
#810=EDGE_CURVE('E711',#660,#792,#809,.T.);
#811=ORIENTED_EDGE('',*,*,#810,.T.);
#812=EDGE_LOOP('',(#794,#801,#802,#811));
#813=FACE_BOUND('',#812,.T.);
#814=ADVANCED_FACE('F725',(#813),#784,.T.);
#815=CARTESIAN_POINT('',(0.,0.,0.));
#816=DIRECTION('',(0.,0.,-1.));
#817=DIRECTION('',(1.,0.,0.));
#818=AXIS2_PLACEMENT_3D('',#815,#816,#817);
#819=CONICAL_SURFACE('',#818,31.75,0.0174532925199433);
#820=ORIENTED_EDGE('',*,*,#661,.F.);
#821=CARTESIAN_POINT('',(-30.1907375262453,-9.84308099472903,-0.274588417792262));
#822=CARTESIAN_POINT('',(-30.1092242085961,-9.81650522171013,4.63723407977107));
#823=B_SPLINE_CURVE_WITH_KNOTS('',1,(#821,#822),.UNSPECIFIED.,.F.,.F.,(2,2),(0.,1.),.UNSPECIFIED.);
#824=EDGE_CURVE('E454',#651,#301,#823,.F.);
#825=ORIENTED_EDGE('',*,*,#824,.T.);
#826=CARTESIAN_POINT('',(0.,0.,0.));
#827=DIRECTION('',(0.,0.,1.));
#828=DIRECTION('',(1.,0.,0.));
#829=AXIS2_PLACEMENT_3D('',#826,#827,#828);
#830=CIRCLE('',#829,31.75);
#831=EDGE_CURVE('E610',#301,#792,#830,.T.);
#832=ORIENTED_EDGE('',*,*,#831,.T.);
#833=ORIENTED_EDGE('',*,*,#810,.F.);
#834=EDGE_LOOP('',(#820,#825,#832,#833));
#835=FACE_BOUND('',#834,.T.);
#836=ADVANCED_FACE('F722',(#835),#819,.T.);
#837=CARTESIAN_POINT('',(-22.6115810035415,10.5439533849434,0.));
#838=DIRECTION('',(-0.906169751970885,0.422553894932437,0.0174524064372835));
#839=DIRECTION('',(-0.422618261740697,-0.906307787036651,0.));
#840=AXIS2_PLACEMENT_3D('',#837,#838,#839);
#841=PLANE('',#840);
#842=DIRECTION('',(-0.422618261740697,-0.906307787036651,0.));
#843=VECTOR('',#842,1.);
#844=CARTESIAN_POINT('',(-22.6115810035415,10.5439533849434,0.));
#845=LINE('',#844,#843);
#846=EDGE_CURVE('E608',#532,#319,#845,.T.);
#847=ORIENTED_EDGE('',*,*,#846,.T.);
#848=DIRECTION('',(-0.0158172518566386,0.00737570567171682,-0.999847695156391));
#849=VECTOR('',#848,1.);
#850=CARTESIAN_POINT('',(-29.8628694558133,-5.09657832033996,2.1813228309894));
#851=LINE('',#850,#849);
#852=EDGE_CURVE('E520',#319,#608,#851,.F.);
#853=ORIENTED_EDGE('',*,*,#852,.T.);
#854=ORIENTED_EDGE('',*,*,#609,.F.);
#855=CARTESIAN_POINT('',(-22.6534203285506,10.4459682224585,0.2));
#856=DIRECTION('',(-0.906169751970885,0.422553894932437,0.0174524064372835));
#857=DIRECTION('',(-0.422914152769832,-0.905397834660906,-0.0373949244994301));
#858=AXIS2_PLACEMENT_3D('',#855,#856,#857);
#859=ELLIPSE('',#858,3.91758827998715,3.55);
#860=EDGE_CURVE('E789',#606,#530,#859,.T.);
#861=ORIENTED_EDGE('',*,*,#860,.T.);
#862=ORIENTED_EDGE('',*,*,#533,.T.);
#863=EDGE_LOOP('',(#847,#853,#854,#861,#862));
#864=FACE_BOUND('',#863,.T.);
#865=ADVANCED_FACE('F741',(#864),#841,.T.);
#866=CARTESIAN_POINT('',(0.,-20.375,0.));
#867=DIRECTION('',(0.,-0.999847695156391,0.0174524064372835));
#868=DIRECTION('',(0.,-0.0174524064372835,-0.999847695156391));
#869=AXIS2_PLACEMENT_3D('',#866,#867,#868);
#870=PLANE('',#869);
#871=DIRECTION('',(1.,0.,0.));
#872=VECTOR('',#871,1.);
#873=CARTESIAN_POINT('',(0.,-20.375,0.));
#874=LINE('',#873,#872);
#875=CARTESIAN_POINT('',(-5.,-20.375,0.));
#876=VERTEX_POINT('',#875);
#877=CARTESIAN_POINT('',(5.,-20.375,0.));
#878=VERTEX_POINT('',#877);
#879=EDGE_CURVE('E611',#876,#878,#874,.T.);
#880=ORIENTED_EDGE('',*,*,#879,.T.);
#881=DIRECTION('',(0.,-0.0174524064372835,-0.999847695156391));
#882=VECTOR('',#881,1.);
#883=CARTESIAN_POINT('',(5.,-20.375,0.));
#884=LINE('',#883,#882);
#885=EDGE_CURVE('E680',#573,#878,#884,.T.);
#886=ORIENTED_EDGE('',*,*,#885,.F.);
#887=ORIENTED_EDGE('',*,*,#597,.F.);
#888=DIRECTION('',(0.,-0.0174524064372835,-0.999847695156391));
#889=VECTOR('',#888,1.);
#890=CARTESIAN_POINT('',(-5.,-20.375,0.));
#891=LINE('',#890,#889);
#892=EDGE_CURVE('E669',#590,#876,#891,.T.);
#893=ORIENTED_EDGE('',*,*,#892,.T.);
#894=EDGE_LOOP('',(#880,#886,#887,#893));
#895=FACE_BOUND('',#894,.T.);
#896=ADVANCED_FACE('F670',(#895),#870,.T.);
#897=CARTESIAN_POINT('',(-5.,-23.375,0.));
#898=DIRECTION('',(0.,0.,1.));
#899=DIRECTION('',(1.,0.,0.));
#900=AXIS2_PLACEMENT_3D('',#897,#898,#899);
#901=CONICAL_SURFACE('',#900,3.,0.0174532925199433);
#902=CARTESIAN_POINT('',(-5.,-23.375,0.));
#903=DIRECTION('',(0.,0.,1.));
#904=DIRECTION('',(1.,0.,0.));
#905=AXIS2_PLACEMENT_3D('',#902,#903,#904);
#906=CIRCLE('',#905,3.);
#907=CARTESIAN_POINT('',(-5.,-26.375,0.));
#908=VERTEX_POINT('',#907);
#909=EDGE_CURVE('E661',#876,#908,#906,.T.);
#910=ORIENTED_EDGE('',*,*,#909,.F.);
#911=ORIENTED_EDGE('',*,*,#892,.F.);
#912=ORIENTED_EDGE('',*,*,#591,.T.);
#913=DIRECTION('',(0.,0.0174524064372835,-0.999847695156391));
#914=VECTOR('',#913,1.);
#915=CARTESIAN_POINT('',(-5.,-26.375,0.));
#916=LINE('',#915,#914);
#917=EDGE_CURVE('E679',#581,#908,#916,.T.);
#918=ORIENTED_EDGE('',*,*,#917,.T.);
#919=EDGE_LOOP('',(#910,#911,#912,#918));
#920=FACE_BOUND('',#919,.T.);
#921=ADVANCED_FACE('F740',(#920),#901,.F.);
#922=CARTESIAN_POINT('',(0.,-26.375,0.));
#923=DIRECTION('',(0.,0.999847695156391,0.0174524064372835));
#924=DIRECTION('',(0.,-0.0174524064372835,0.999847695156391));
#925=AXIS2_PLACEMENT_3D('',#922,#923,#924);
#926=PLANE('',#925);
#927=DIRECTION('',(1.,0.,0.));
#928=VECTOR('',#927,1.);
#929=CARTESIAN_POINT('',(0.,-26.375,0.));
#930=LINE('',#929,#928);
#931=CARTESIAN_POINT('',(5.,-26.375,0.));
#932=VERTEX_POINT('',#931);
#933=EDGE_CURVE('E837',#908,#932,#930,.T.);
#934=ORIENTED_EDGE('',*,*,#933,.F.);
#935=ORIENTED_EDGE('',*,*,#917,.F.);
#936=ORIENTED_EDGE('',*,*,#582,.T.);
#937=DIRECTION('',(0.,0.0174524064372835,-0.999847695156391));
#938=VECTOR('',#937,1.);
#939=CARTESIAN_POINT('',(5.,-26.375,0.));
#940=LINE('',#939,#938);
#941=EDGE_CURVE('E683',#571,#932,#940,.T.);
#942=ORIENTED_EDGE('',*,*,#941,.T.);
#943=EDGE_LOOP('',(#934,#935,#936,#942));
#944=FACE_BOUND('',#943,.T.);
#945=ADVANCED_FACE('F736',(#944),#926,.T.);
#946=CARTESIAN_POINT('',(5.,-23.375,0.));
#947=DIRECTION('',(0.,0.,1.));
#948=DIRECTION('',(1.,0.,0.));
#949=AXIS2_PLACEMENT_3D('',#946,#947,#948);
#950=CONICAL_SURFACE('',#949,3.,0.0174532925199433);
#951=CARTESIAN_POINT('',(5.,-23.375,0.));
#952=DIRECTION('',(0.,0.,1.));
#953=DIRECTION('',(1.,0.,0.));
#954=AXIS2_PLACEMENT_3D('',#951,#952,#953);
#955=CIRCLE('',#954,3.);
#956=EDGE_CURVE('E720',#932,#878,#955,.T.);
#957=ORIENTED_EDGE('',*,*,#956,.F.);
#958=ORIENTED_EDGE('',*,*,#941,.F.);
#959=ORIENTED_EDGE('',*,*,#574,.T.);
#960=ORIENTED_EDGE('',*,*,#885,.T.);
#961=EDGE_LOOP('',(#957,#958,#959,#960));
#962=FACE_BOUND('',#961,.T.);
#963=ADVANCED_FACE('F586',(#962),#950,.F.);
#964=CARTESIAN_POINT('',(-22.6115810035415,10.5439533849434,0.));
#965=DIRECTION('',(-0.906169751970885,0.422553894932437,-0.0174524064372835));
#966=DIRECTION('',(-0.422618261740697,-0.906307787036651,0.));
#967=AXIS2_PLACEMENT_3D('',#964,#965,#966);
#968=PLANE('',#967);
#969=DIRECTION('',(-0.422618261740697,-0.906307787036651,0.));
#970=VECTOR('',#969,1.);
#971=CARTESIAN_POINT('',(-22.5522572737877,10.5162902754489,-3.75));
#972=LINE('',#971,#970);
#973=CARTESIAN_POINT('',(-22.5850489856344,10.4459682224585,-3.75));
#974=VERTEX_POINT('',#973);
#975=EDGE_CURVE('E527',#974,#341,#972,.T.);
#976=ORIENTED_EDGE('',*,*,#975,.T.);
#977=ORIENTED_EDGE('',*,*,#342,.T.);
#978=ORIENTED_EDGE('',*,*,#846,.F.);
#979=DIRECTION('',(-0.0111177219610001,0.0174513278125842,0.999785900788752));
#980=VECTOR('',#979,1.);
#981=CARTESIAN_POINT('',(-20.9974043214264,13.9959256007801,-0.233422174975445));
#982=LINE('',#981,#980);
#983=CARTESIAN_POINT('',(-20.9970870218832,13.9954275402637,-0.261956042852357));
#984=VERTEX_POINT('',#983);
#985=EDGE_CURVE('E551',#984,#532,#982,.T.);
#986=ORIENTED_EDGE('',*,*,#985,.F.);
#987=CARTESIAN_POINT('',(-22.6534203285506,10.4459682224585,-0.2));
#988=DIRECTION('',(-0.906169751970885,0.422553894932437,-0.0174524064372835));
#989=DIRECTION('',(0.422914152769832,0.905397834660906,-0.0373949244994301));
#990=AXIS2_PLACEMENT_3D('',#987,#988,#989);
#991=ELLIPSE('',#990,3.91758827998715,3.55);
#992=EDGE_CURVE('E967',#984,#974,#991,.T.);
#993=ORIENTED_EDGE('',*,*,#992,.T.);
#994=EDGE_LOOP('',(#976,#977,#978,#986,#993));
#995=FACE_BOUND('',#994,.T.);
#996=ADVANCED_FACE('F582',(#995),#968,.T.);
#997=CARTESIAN_POINT('',(0.,14.,0.));
#998=DIRECTION('',(0.,0.999847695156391,-0.0174524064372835));
#999=DIRECTION('',(0.,0.0174524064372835,0.999847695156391));
#1000=AXIS2_PLACEMENT_3D('',#997,#998,#999);
#1001=PLANE('',#1000);
#1002=DIRECTION('',(0.0174497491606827,0.0174497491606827,0.999695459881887));
#1003=VECTOR('',#1002,1.);
#1004=CARTESIAN_POINT('',(-15.0042629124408,13.9957370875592,-0.244222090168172));
#1005=LINE('',#1004,#1003);
#1006=CARTESIAN_POINT('',(-15.0045724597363,13.9954275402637,-0.261956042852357));
#1007=VERTEX_POINT('',#1006);
#1008=EDGE_CURVE('E555',#1007,#548,#1005,.T.);
#1009=ORIENTED_EDGE('',*,*,#1008,.F.);
#1010=DIRECTION('',(-1.,0.,0.));
#1011=VECTOR('',#1010,1.);
#1012=CARTESIAN_POINT('',(-20.9582996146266,13.9954275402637,-0.261956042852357));
#1013=LINE('',#1012,#1011);
#1014=EDGE_CURVE('E554',#1007,#984,#1013,.T.);
#1015=ORIENTED_EDGE('',*,*,#1014,.T.);
#1016=ORIENTED_EDGE('',*,*,#985,.T.);
#1017=ORIENTED_EDGE('',*,*,#555,.F.);
#1018=EDGE_LOOP('',(#1009,#1015,#1016,#1017));
#1019=FACE_BOUND('',#1018,.T.);
#1020=ADVANCED_FACE('F585',(#1019),#1001,.T.);
#1021=CARTESIAN_POINT('',(-15.,0.,0.));
#1022=DIRECTION('',(0.999847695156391,0.,-0.0174524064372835));
#1023=DIRECTION('',(-0.0174524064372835,0.,-0.999847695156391));
#1024=AXIS2_PLACEMENT_3D('',#1021,#1022,#1023);
#1025=PLANE('',#1024);
#1026=DIRECTION('',(0.,1.,0.));
#1027=VECTOR('',#1026,1.);
#1028=CARTESIAN_POINT('',(-15.0654564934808,0.,-3.75));
#1029=LINE('',#1028,#1027);
#1030=CARTESIAN_POINT('',(-15.0654564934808,10.4459682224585,-3.75));
#1031=VERTEX_POINT('',#1030);
#1032=EDGE_CURVE('E649',#475,#1031,#1029,.T.);
#1033=ORIENTED_EDGE('',*,*,#1032,.T.);
#1034=CARTESIAN_POINT('',(-15.0034910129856,10.4459682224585,-0.2));
#1035=DIRECTION('',(0.999847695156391,0.,-0.0174524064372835));
#1036=DIRECTION('',(0.0174524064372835,0.,0.999847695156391));
#1037=AXIS2_PLACEMENT_3D('',#1034,#1035,#1036);
#1038=ELLIPSE('',#1037,3.55054076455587,3.55);
#1039=EDGE_CURVE('E971',#1031,#1007,#1038,.T.);
#1040=ORIENTED_EDGE('',*,*,#1039,.T.);
#1041=ORIENTED_EDGE('',*,*,#1008,.T.);
#1042=ORIENTED_EDGE('',*,*,#738,.F.);
#1043=ORIENTED_EDGE('',*,*,#484,.F.);
#1044=EDGE_LOOP('',(#1033,#1040,#1041,#1042,#1043));
#1045=FACE_BOUND('',#1044,.T.);
#1046=ADVANCED_FACE('F980',(#1045),#1025,.T.);
#1047=CARTESIAN_POINT('',(28.479426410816,0.,0.));
#1048=DIRECTION('',(0.999847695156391,0.,-0.0174524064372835));
#1049=DIRECTION('',(-0.0174524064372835,0.,-0.999847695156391));
#1050=AXIS2_PLACEMENT_3D('',#1047,#1048,#1049);
#1051=PLANE('',#1050);
#1052=CARTESIAN_POINT('',(28.474818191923,10.45,-0.264004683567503));
#1053=DIRECTION('',(0.999847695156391,0.,-0.0174524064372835));
#1054=DIRECTION('',(-0.0174524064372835,0.,-0.999847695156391));
#1055=AXIS2_PLACEMENT_3D('',#1052,#1053,#1054);
#1056=CIRCLE('',#1055,6.5);
#1057=CARTESIAN_POINT('',(28.4139699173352,4.96418792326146,-3.75));
#1058=VERTEX_POINT('',#1057);
#1059=EDGE_CURVE('E433',#790,#1058,#1056,.T.);
#1060=ORIENTED_EDGE('',*,*,#1059,.F.);
#1061=ORIENTED_EDGE('',*,*,#793,.T.);
#1062=CARTESIAN_POINT('',(28.4139699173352,-14.0198648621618,-3.75));
#1063=CARTESIAN_POINT('',(28.4248793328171,-14.022409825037,-3.12500000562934));
#1064=CARTESIAN_POINT('',(28.4357887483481,-14.0249540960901,-2.50000000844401));
#1065=CARTESIAN_POINT('',(28.4576075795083,-14.0300412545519,-1.25000000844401));
#1066=CARTESIAN_POINT('',(28.4685169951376,-14.0325841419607,-0.625000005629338));
#1067=CARTESIAN_POINT('',(28.479426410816,-14.0351263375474,0.));
#1068=B_SPLINE_CURVE_WITH_KNOTS('',3,(#1062,#1063,#1064,#1065,#1066,#1067),.UNSPECIFIED.,.F.,
.F.,(4,2,4),(0.,1.87530114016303,3.75060228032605),.UNSPECIFIED.);
#1069=CARTESIAN_POINT('',(28.4139699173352,-14.0198648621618,-3.75));
#1070=VERTEX_POINT('',#1069);
#1071=EDGE_CURVE('E556',#1070,#792,#1068,.T.);
#1072=ORIENTED_EDGE('',*,*,#1071,.F.);
#1073=DIRECTION('',(0.,1.,0.));
#1074=VECTOR('',#1073,1.);
#1075=CARTESIAN_POINT('',(28.4139699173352,0.,-3.75));
#1076=LINE('',#1075,#1074);
#1077=EDGE_CURVE('E532',#1058,#1070,#1076,.F.);
#1078=ORIENTED_EDGE('',*,*,#1077,.F.);
#1079=EDGE_LOOP('',(#1060,#1061,#1072,#1078));
#1080=FACE_BOUND('',#1079,.T.);
#1081=ADVANCED_FACE('F574',(#1080),#1051,.T.);
#1082=CARTESIAN_POINT('',(5.,-23.375,0.));
#1083=DIRECTION('',(0.,0.,-1.));
#1084=DIRECTION('',(1.,0.,0.));
#1085=AXIS2_PLACEMENT_3D('',#1082,#1083,#1084);
#1086=CONICAL_SURFACE('',#1085,3.,0.0174532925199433);
#1087=ORIENTED_EDGE('',*,*,#956,.T.);
#1088=DIRECTION('',(0.,-0.0174524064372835,0.999847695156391));
#1089=VECTOR('',#1088,1.);
#1090=CARTESIAN_POINT('',(5.,-20.375,0.));
#1091=LINE('',#1090,#1089);
#1092=CARTESIAN_POINT('',(5.,-20.3095435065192,-3.75));
#1093=VERTEX_POINT('',#1092);
#1094=EDGE_CURVE('E566',#1093,#878,#1091,.T.);
#1095=ORIENTED_EDGE('',*,*,#1094,.F.);
#1096=CARTESIAN_POINT('',(5.,-23.375,-3.75));
#1097=DIRECTION('',(0.,0.,1.));
#1098=DIRECTION('',(1.,0.,0.));
#1099=AXIS2_PLACEMENT_3D('',#1096,#1097,#1098);
#1100=CIRCLE('',#1099,3.06545649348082);
#1101=CARTESIAN_POINT('',(5.,-26.4404564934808,-3.75));
#1102=VERTEX_POINT('',#1101);
#1103=EDGE_CURVE('E546',#1102,#1093,#1100,.T.);
#1104=ORIENTED_EDGE('',*,*,#1103,.F.);
#1105=DIRECTION('',(0.,0.0174524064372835,0.999847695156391));
#1106=VECTOR('',#1105,1.);
#1107=CARTESIAN_POINT('',(5.,-26.375,0.));
#1108=LINE('',#1107,#1106);
#1109=EDGE_CURVE('E645',#1102,#932,#1108,.T.);
#1110=ORIENTED_EDGE('',*,*,#1109,.T.);
#1111=EDGE_LOOP('',(#1087,#1095,#1104,#1110));
#1112=FACE_BOUND('',#1111,.T.);
#1113=ADVANCED_FACE('F852',(#1112),#1086,.F.);
#1114=CARTESIAN_POINT('',(0.,-20.375,0.));
#1115=DIRECTION('',(0.,-0.999847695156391,-0.0174524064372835));
#1116=DIRECTION('',(0.,0.0174524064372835,-0.999847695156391));
#1117=AXIS2_PLACEMENT_3D('',#1114,#1115,#1116);
#1118=PLANE('',#1117);
#1119=ORIENTED_EDGE('',*,*,#879,.F.);
#1120=DIRECTION('',(0.,-0.0174524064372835,0.999847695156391));
#1121=VECTOR('',#1120,1.);
#1122=CARTESIAN_POINT('',(-5.,-20.375,0.));
#1123=LINE('',#1122,#1121);
#1124=CARTESIAN_POINT('',(-5.,-20.3095435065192,-3.75));
#1125=VERTEX_POINT('',#1124);
#1126=EDGE_CURVE('E644',#1125,#876,#1123,.T.);
#1127=ORIENTED_EDGE('',*,*,#1126,.F.);
#1128=DIRECTION('',(1.,0.,0.));
#1129=VECTOR('',#1128,1.);
#1130=CARTESIAN_POINT('',(0.,-20.3095435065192,-3.75));
#1131=LINE('',#1130,#1129);
#1132=EDGE_CURVE('E529',#1125,#1093,#1131,.T.);
#1133=ORIENTED_EDGE('',*,*,#1132,.T.);
#1134=ORIENTED_EDGE('',*,*,#1094,.T.);
#1135=EDGE_LOOP('',(#1119,#1127,#1133,#1134));
#1136=FACE_BOUND('',#1135,.T.);
#1137=ADVANCED_FACE('F989',(#1136),#1118,.T.);
#1138=CARTESIAN_POINT('',(-5.,-23.375,0.));
#1139=DIRECTION('',(0.,0.,-1.));
#1140=DIRECTION('',(1.,0.,0.));
#1141=AXIS2_PLACEMENT_3D('',#1138,#1139,#1140);
#1142=CONICAL_SURFACE('',#1141,3.,0.0174532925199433);
#1143=ORIENTED_EDGE('',*,*,#909,.T.);
#1144=DIRECTION('',(0.,0.0174524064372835,0.999847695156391));
#1145=VECTOR('',#1144,1.);
#1146=CARTESIAN_POINT('',(-5.,-26.375,0.));
#1147=LINE('',#1146,#1145);
#1148=CARTESIAN_POINT('',(-5.,-26.4404564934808,-3.75));
#1149=VERTEX_POINT('',#1148);
#1150=EDGE_CURVE('E648',#1149,#908,#1147,.T.);
#1151=ORIENTED_EDGE('',*,*,#1150,.F.);
#1152=CARTESIAN_POINT('',(-5.,-23.375,-3.75));
#1153=DIRECTION('',(0.,0.,1.));
#1154=DIRECTION('',(1.,0.,0.));
#1155=AXIS2_PLACEMENT_3D('',#1152,#1153,#1154);
#1156=CIRCLE('',#1155,3.06545649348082);
#1157=EDGE_CURVE('E535',#1125,#1149,#1156,.T.);
#1158=ORIENTED_EDGE('',*,*,#1157,.F.);
#1159=ORIENTED_EDGE('',*,*,#1126,.T.);
#1160=EDGE_LOOP('',(#1143,#1151,#1158,#1159));
#1161=FACE_BOUND('',#1160,.T.);
#1162=ADVANCED_FACE('F657',(#1161),#1142,.F.);
#1163=CARTESIAN_POINT('',(0.,-26.375,0.));
#1164=DIRECTION('',(0.,0.999847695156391,-0.0174524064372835));
#1165=DIRECTION('',(0.,0.0174524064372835,0.999847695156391));
#1166=AXIS2_PLACEMENT_3D('',#1163,#1164,#1165);
#1167=PLANE('',#1166);
#1168=ORIENTED_EDGE('',*,*,#933,.T.);
#1169=ORIENTED_EDGE('',*,*,#1109,.F.);
#1170=DIRECTION('',(-1.,0.,0.));
#1171=VECTOR('',#1170,1.);
#1172=CARTESIAN_POINT('',(0.,-26.4404564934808,-3.75));
#1173=LINE('',#1172,#1171);
#1174=EDGE_CURVE('E543',#1149,#1102,#1173,.F.);
#1175=ORIENTED_EDGE('',*,*,#1174,.F.);
#1176=ORIENTED_EDGE('',*,*,#1150,.T.);
#1177=EDGE_LOOP('',(#1168,#1169,#1175,#1176));
#1178=FACE_BOUND('',#1177,.T.);
#1179=ADVANCED_FACE('F581',(#1178),#1167,.T.);
#1180=CARTESIAN_POINT('',(0.,0.,0.));
#1181=DIRECTION('',(0.,0.,1.));
#1182=DIRECTION('',(1.,0.,0.));
#1183=AXIS2_PLACEMENT_3D('',#1180,#1181,#1182);
#1184=CONICAL_SURFACE('',#1183,31.75,0.0174532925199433);
#1185=ORIENTED_EDGE('',*,*,#831,.F.);
#1186=ORIENTED_EDGE('',*,*,#304,.T.);
#1187=CARTESIAN_POINT('',(0.,0.,-3.75));
#1188=DIRECTION('',(0.,0.,1.));
#1189=DIRECTION('',(1.,0.,0.));
#1190=AXIS2_PLACEMENT_3D('',#1187,#1188,#1189);
#1191=CIRCLE('',#1190,31.6845435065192);
#1192=EDGE_CURVE('E528',#303,#1070,#1191,.T.);
#1193=ORIENTED_EDGE('',*,*,#1192,.T.);
#1194=ORIENTED_EDGE('',*,*,#1071,.T.);
#1195=EDGE_LOOP('',(#1185,#1186,#1193,#1194));
#1196=FACE_BOUND('',#1195,.T.);
#1197=ADVANCED_FACE('F576',(#1196),#1184,.T.);
#1198=CARTESIAN_POINT('',(0.,0.,-3.75));
#1199=DIRECTION('',(0.,0.,1.));
#1200=DIRECTION('',(1.,0.,0.));
#1201=AXIS2_PLACEMENT_3D('',#1198,#1199,#1200);
#1202=PLANE('',#1201);
#1203=ORIENTED_EDGE('',*,*,#1192,.F.);
#1204=ORIENTED_EDGE('',*,*,#382,.T.);
#1205=ORIENTED_EDGE('',*,*,#975,.F.);
#1206=DIRECTION('',(-1.,0.,0.));
#1207=VECTOR('',#1206,1.);
#1208=CARTESIAN_POINT('',(-15.0654564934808,10.4459682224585,-3.75));
#1209=LINE('',#1208,#1207);
#1210=EDGE_CURVE('E969',#974,#1031,#1209,.F.);
#1211=ORIENTED_EDGE('',*,*,#1210,.T.);
#1212=ORIENTED_EDGE('',*,*,#1032,.F.);
#1213=ORIENTED_EDGE('',*,*,#476,.T.);
#1214=ORIENTED_EDGE('',*,*,#514,.T.);
#1215=CARTESIAN_POINT('',(228.187356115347,10.45,-3.75));
#1216=DIRECTION('',(0.,0.,1.));
#1217=DIRECTION('',(-1.,0.,0.));
#1218=AXIS2_PLACEMENT_3D('',#1215,#1216,#1217);
#1219=ELLIPSE('',#1218,372.441475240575,6.5);
#1220=EDGE_CURVE('E523',#1058,#507,#1219,.F.);
#1221=ORIENTED_EDGE('',*,*,#1220,.F.);
#1222=ORIENTED_EDGE('',*,*,#1077,.T.);
#1223=EDGE_LOOP('',(#1203,#1204,#1205,#1211,#1212,#1213,#1214,#1221,#1222));
#1224=FACE_BOUND('',#1223,.T.);
#1225=ORIENTED_EDGE('',*,*,#1103,.T.);
#1226=ORIENTED_EDGE('',*,*,#1132,.F.);
#1227=ORIENTED_EDGE('',*,*,#1157,.T.);
#1228=ORIENTED_EDGE('',*,*,#1174,.T.);
#1229=EDGE_LOOP('',(#1225,#1226,#1227,#1228));
#1230=FACE_BOUND('',#1229,.T.);
#1231=ADVANCED_FACE('F580',(#1224,#1230),#1202,.F.);
#1232=CARTESIAN_POINT('',(0.,10.4459682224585,-0.2));
#1233=DIRECTION('',(1.,0.,0.));
#1234=DIRECTION('',(0.,1.,0.));
#1235=AXIS2_PLACEMENT_3D('',#1232,#1233,#1234);
#1236=CYLINDRICAL_SURFACE('',#1235,3.55);
#1237=ORIENTED_EDGE('',*,*,#1039,.F.);
#1238=ORIENTED_EDGE('',*,*,#1210,.F.);
#1239=ORIENTED_EDGE('',*,*,#992,.F.);
#1240=ORIENTED_EDGE('',*,*,#1014,.F.);
#1241=EDGE_LOOP('',(#1237,#1238,#1239,#1240));
#1242=FACE_BOUND('',#1241,.T.);
#1243=ADVANCED_FACE('F762',(#1242),#1236,.T.);
#1244=CARTESIAN_POINT('',(0.,10.4459682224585,0.2));
#1245=DIRECTION('',(-1.,0.,0.));
#1246=DIRECTION('',(0.,-1.,0.));
#1247=AXIS2_PLACEMENT_3D('',#1244,#1245,#1246);
#1248=CYLINDRICAL_SURFACE('',#1247,3.55);
#1249=ORIENTED_EDGE('',*,*,#725,.F.);
#1250=ORIENTED_EDGE('',*,*,#541,.F.);
#1251=ORIENTED_EDGE('',*,*,#860,.F.);
#1252=ORIENTED_EDGE('',*,*,#709,.F.);
#1253=EDGE_LOOP('',(#1249,#1250,#1251,#1252));
#1254=FACE_BOUND('',#1253,.T.);
#1255=ADVANCED_FACE('F469',(#1254),#1248,.T.);
#1256=CARTESIAN_POINT('',(29.5975250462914,10.45,-0.283601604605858));
#1257=DIRECTION('',(-0.999847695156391,0.,0.0174524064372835));
#1258=DIRECTION('',(0.0174524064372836,0.,0.999847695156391));
#1259=AXIS2_PLACEMENT_3D('',#1256,#1257,#1258);
#1260=CYLINDRICAL_SURFACE('',#1259,6.5);
#1261=ORIENTED_EDGE('',*,*,#774,.F.);
#1262=ORIENTED_EDGE('',*,*,#678,.F.);
#1263=ORIENTED_EDGE('',*,*,#800,.F.);
#1264=ORIENTED_EDGE('',*,*,#1059,.T.);
#1265=ORIENTED_EDGE('',*,*,#1220,.T.);
#1266=ORIENTED_EDGE('',*,*,#508,.T.);
#1267=ORIENTED_EDGE('',*,*,#456,.T.);
#1268=EDGE_LOOP('',(#1261,#1262,#1263,#1264,#1265,#1266,#1267));
#1269=FACE_BOUND('',#1268,.T.);
#1270=CARTESIAN_POINT('',(29.6074286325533,10.45,-0.283774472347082));
#1271=DIRECTION('',(0.999847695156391,0.,0.0174524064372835));
#1272=DIRECTION('',(-0.0174524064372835,0.,0.999847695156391));
#1273=AXIS2_PLACEMENT_3D('',#1270,#1271,#1272);
#1274=ELLIPSE('',#1273,6.50396203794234,6.5);
#1275=EDGE_CURVE('E429',#428,#426,#1274,.T.);
#1276=ORIENTED_EDGE('',*,*,#1275,.F.);
#1277=ORIENTED_EDGE('',*,*,#429,.F.);
#1278=EDGE_LOOP('',(#1276,#1277));
#1279=FACE_BOUND('',#1278,.T.);
#1280=ORIENTED_EDGE('',*,*,#404,.T.);
#1281=CARTESIAN_POINT('',(13.35,10.45,0.));
#1282=DIRECTION('',(-0.999847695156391,0.,-0.0174524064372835));
#1283=DIRECTION('',(-0.0174524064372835,0.,0.999847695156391));
#1284=AXIS2_PLACEMENT_3D('',#1281,#1282,#1283);
#1285=ELLIPSE('',#1284,6.50396203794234,6.5);
#1286=EDGE_CURVE('E600',#403,#401,#1285,.F.);
#1287=ORIENTED_EDGE('',*,*,#1286,.T.);
#1288=EDGE_LOOP('',(#1280,#1287));
#1289=FACE_BOUND('',#1288,.T.);
#1290=ADVANCED_FACE('F427',(#1269,#1279,#1289),#1260,.T.);
#1291=CARTESIAN_POINT('',(29.6024753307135,0.,0.));
#1292=DIRECTION('',(0.999847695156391,0.,0.0174524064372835));
#1293=DIRECTION('',(0.0174524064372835,0.,-0.999847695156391));
#1294=AXIS2_PLACEMENT_3D('',#1291,#1292,#1293);
#1295=PLANE('',#1294);
#1296=ORIENTED_EDGE('',*,*,#435,.F.);
#1297=ORIENTED_EDGE('',*,*,#1275,.T.);
#1298=EDGE_LOOP('',(#1296,#1297));
#1299=FACE_BOUND('',#1298,.T.);
#1300=ADVANCED_FACE('F432',(#1299),#1295,.T.);
#1301=CARTESIAN_POINT('',(13.35,0.,0.));
#1302=DIRECTION('',(-0.999847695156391,0.,-0.0174524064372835));
#1303=DIRECTION('',(-0.0174524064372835,0.,0.999847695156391));
#1304=AXIS2_PLACEMENT_3D('',#1301,#1302,#1303);
#1305=PLANE('',#1304);
#1306=ORIENTED_EDGE('',*,*,#410,.F.);
#1307=ORIENTED_EDGE('',*,*,#1286,.F.);
#1308=EDGE_LOOP('',(#1306,#1307));
#1309=FACE_BOUND('',#1308,.T.);
#1310=ADVANCED_FACE('F468',(#1309),#1305,.T.);
#1311=CARTESIAN_POINT('',(-30.1755847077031,-9.88955778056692,-0.274588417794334));
#1312=CARTESIAN_POINT('',(-30.1806356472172,-9.87406551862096,-0.274588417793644));
#1313=CARTESIAN_POINT('',(-30.1856865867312,-9.85857325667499,-0.274588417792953));
#1314=CARTESIAN_POINT('',(-30.1907375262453,-9.84308099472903,-0.274588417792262));
#1315=CARTESIAN_POINT('',(-30.4432845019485,-9.06846789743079,-0.274588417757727));
#1316=CARTESIAN_POINT('',(-30.5484698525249,-8.2463833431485,-0.27448820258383));
#1317=CARTESIAN_POINT('',(-30.4498253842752,-6.62019718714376,-0.27448820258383));
#1318=CARTESIAN_POINT('',(-30.2460419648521,-5.81685987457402,-0.27458841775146));
#1319=CARTESIAN_POINT('',(-29.9017211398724,-5.07846148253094,-0.274588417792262));
#1320=CARTESIAN_POINT('',(-30.0942711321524,-9.86236935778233,4.63723407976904));
#1321=CARTESIAN_POINT('',(-30.099255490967,-9.84708131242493,4.63723407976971));
#1322=CARTESIAN_POINT('',(-30.1042398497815,-9.83179326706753,4.63723407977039));
#1323=CARTESIAN_POINT('',(-30.1092242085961,-9.81650522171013,4.63723407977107));
#1324=CARTESIAN_POINT('',(-30.3584421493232,-9.05210295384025,4.63723407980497));
#1325=CARTESIAN_POINT('',(-30.4622407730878,-8.24085573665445,4.6373342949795));
#1326=CARTESIAN_POINT('',(-30.3648967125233,-6.63610722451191,4.6373342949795));
#1327=CARTESIAN_POINT('',(-30.1637998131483,-5.84336009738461,4.63723407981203));
#1328=CARTESIAN_POINT('',(-29.8240177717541,-5.11469515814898,4.63723407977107));
#1329=B_SPLINE_SURFACE_WITH_KNOTS('',1,3,((#1311,#1312,#1313,#1314,#1315,#1316,#1317,#1318,
#1319),(#1320,#1321,#1322,#1323,#1324,#1325,#1326,#1327,#1328)),.UNSPECIFIED.,.F.,.F.,.F.,(2,2),
(4,3,2,4),(0.,1.),(-0.01,0.,0.5,1.),.UNSPECIFIED.);
#1330=ORIENTED_EDGE('',*,*,#320,.F.);
#1331=ORIENTED_EDGE('',*,*,#824,.F.);
#1332=ORIENTED_EDGE('',*,*,#652,.F.);
#1333=ORIENTED_EDGE('',*,*,#852,.F.);
#1334=EDGE_LOOP('',(#1330,#1331,#1332,#1333));
#1335=FACE_BOUND('',#1334,.T.);
#1336=ADVANCED_FACE('F456',(#1335),#1329,.T.);
#1337=CLOSED_SHELL('',(#389,#414,#439,#495,#519,#559,#713,#742,#762,#779,#814,#836,#865,#896,
#921,#945,#963,#996,#1020,#1046,#1081,#1113,#1137,#1162,#1179,#1197,#1231,#1243,#1255,#1290,
#1300,#1310,#1336));
#1338=MANIFOLD_SOLID_BREP('B7',#1337);
#1339=ADVANCED_BREP_SHAPE_REPRESENTATION('',(#18,#270,#1338),#14);
#1340=SHAPE_DEFINITION_REPRESENTATION(#9,#1339);
ENDSEC;
END-ISO-10303-21;
